VERSION 5.8 ;
BUSBITCHARS "[]" ;
DIVIDERCHAR "/" ;
UNITS
    DATABASE MICRONS 1000 ;
END UNITS

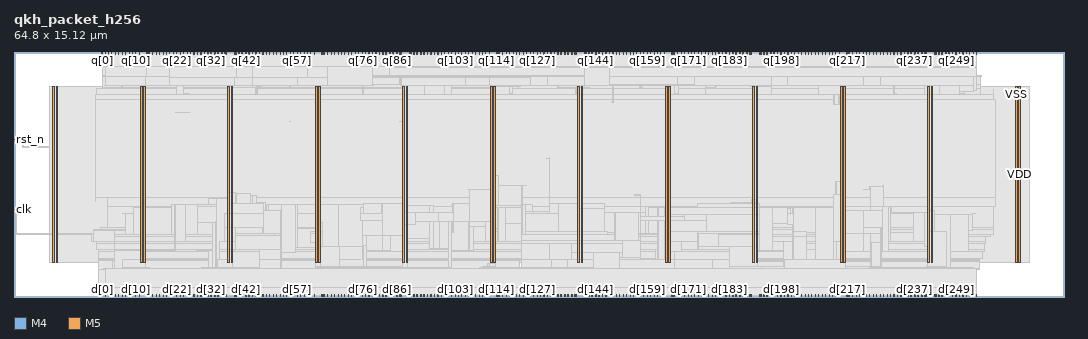
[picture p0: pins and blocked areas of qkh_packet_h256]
MACRO qkh_packet_h256
  FOREIGN qkh_packet_h256 0 0 ;
  CLASS BLOCK ;
  SIZE 64.8 BY 15.12 ;
  PIN clk
    DIRECTION INPUT ;
    USE SIGNAL ;
    PORT
      LAYER M4 ;
        RECT  0.054 5.376 0.138 5.4 ;
    END
    PORT
      LAYER M4 ;
        RECT  0.108 5.376 0.179 5.4 ;
    END
  END clk
  PIN d[0]
    DIRECTION INPUT ;
    USE SIGNAL ;
    PORT
      LAYER M5 ;
        RECT  5.424 0.054 5.448 0.138 ;
    END
  END d[0]
  PIN d[100]
    DIRECTION INPUT ;
    USE SIGNAL ;
    PORT
      LAYER M5 ;
        RECT  26.544 0.054 26.568 0.138 ;
    END
  END d[100]
  PIN d[101]
    DIRECTION INPUT ;
    USE SIGNAL ;
    PORT
      LAYER M5 ;
        RECT  26.784 0.054 26.808 0.138 ;
    END
  END d[101]
  PIN d[102]
    DIRECTION INPUT ;
    USE SIGNAL ;
    PORT
      LAYER M5 ;
        RECT  26.976 0.054 27 0.138 ;
    END
  END d[102]
  PIN d[103]
    DIRECTION INPUT ;
    USE SIGNAL ;
    PORT
      LAYER M5 ;
        RECT  27.216 0.054 27.24 0.138 ;
    END
  END d[103]
  PIN d[104]
    DIRECTION INPUT ;
    USE SIGNAL ;
    PORT
      LAYER M5 ;
        RECT  27.408 0.054 27.432 0.138 ;
    END
  END d[104]
  PIN d[105]
    DIRECTION INPUT ;
    USE SIGNAL ;
    PORT
      LAYER M5 ;
        RECT  27.6 0.054 27.624 0.138 ;
    END
  END d[105]
  PIN d[106]
    DIRECTION INPUT ;
    USE SIGNAL ;
    PORT
      LAYER M5 ;
        RECT  27.84 0.054 27.864 0.138 ;
    END
  END d[106]
  PIN d[107]
    DIRECTION INPUT ;
    USE SIGNAL ;
    PORT
      LAYER M5 ;
        RECT  28.032 0.054 28.056 0.138 ;
    END
  END d[107]
  PIN d[108]
    DIRECTION INPUT ;
    USE SIGNAL ;
    PORT
      LAYER M5 ;
        RECT  28.272 0.054 28.296 0.138 ;
    END
  END d[108]
  PIN d[109]
    DIRECTION INPUT ;
    USE SIGNAL ;
    PORT
      LAYER M5 ;
        RECT  28.464 0.054 28.488 0.138 ;
    END
  END d[109]
  PIN d[10]
    DIRECTION INPUT ;
    USE SIGNAL ;
    PORT
      LAYER M5 ;
        RECT  7.488 0.054 7.512 0.138 ;
    END
  END d[10]
  PIN d[110]
    DIRECTION INPUT ;
    USE SIGNAL ;
    PORT
      LAYER M5 ;
        RECT  28.704 0.054 28.728 0.138 ;
    END
  END d[110]
  PIN d[111]
    DIRECTION INPUT ;
    USE SIGNAL ;
    PORT
      LAYER M5 ;
        RECT  28.896 0.054 28.92 0.138 ;
    END
  END d[111]
  PIN d[112]
    DIRECTION INPUT ;
    USE SIGNAL ;
    PORT
      LAYER M5 ;
        RECT  29.088 0.054 29.112 0.138 ;
    END
  END d[112]
  PIN d[113]
    DIRECTION INPUT ;
    USE SIGNAL ;
    PORT
      LAYER M5 ;
        RECT  29.328 0.054 29.352 0.138 ;
    END
  END d[113]
  PIN d[114]
    DIRECTION INPUT ;
    USE SIGNAL ;
    PORT
      LAYER M5 ;
        RECT  29.76 0.054 29.784 0.138 ;
    END
  END d[114]
  PIN d[115]
    DIRECTION INPUT ;
    USE SIGNAL ;
    PORT
      LAYER M5 ;
        RECT  29.856 0.054 29.88 0.138 ;
    END
  END d[115]
  PIN d[116]
    DIRECTION INPUT ;
    USE SIGNAL ;
    PORT
      LAYER M5 ;
        RECT  29.952 0.054 29.976 0.138 ;
    END
  END d[116]
  PIN d[117]
    DIRECTION INPUT ;
    USE SIGNAL ;
    PORT
      LAYER M5 ;
        RECT  30.144 0.054 30.168 0.138 ;
    END
  END d[117]
  PIN d[118]
    DIRECTION INPUT ;
    USE SIGNAL ;
    PORT
      LAYER M5 ;
        RECT  30.384 0.054 30.408 0.138 ;
    END
  END d[118]
  PIN d[119]
    DIRECTION INPUT ;
    USE SIGNAL ;
    PORT
      LAYER M5 ;
        RECT  30.576 0.054 30.6 0.138 ;
    END
  END d[119]
  PIN d[11]
    DIRECTION INPUT ;
    USE SIGNAL ;
    PORT
      LAYER M5 ;
        RECT  7.728 0.054 7.752 0.138 ;
    END
  END d[11]
  PIN d[120]
    DIRECTION INPUT ;
    USE SIGNAL ;
    PORT
      LAYER M5 ;
        RECT  30.816 0.054 30.84 0.138 ;
    END
  END d[120]
  PIN d[121]
    DIRECTION INPUT ;
    USE SIGNAL ;
    PORT
      LAYER M5 ;
        RECT  31.008 0.054 31.032 0.138 ;
    END
  END d[121]
  PIN d[122]
    DIRECTION INPUT ;
    USE SIGNAL ;
    PORT
      LAYER M5 ;
        RECT  31.2 0.054 31.224 0.138 ;
    END
  END d[122]
  PIN d[123]
    DIRECTION INPUT ;
    USE SIGNAL ;
    PORT
      LAYER M5 ;
        RECT  31.44 0.054 31.464 0.138 ;
    END
  END d[123]
  PIN d[124]
    DIRECTION INPUT ;
    USE SIGNAL ;
    PORT
      LAYER M5 ;
        RECT  31.632 0.054 31.656 0.138 ;
    END
  END d[124]
  PIN d[125]
    DIRECTION INPUT ;
    USE SIGNAL ;
    PORT
      LAYER M5 ;
        RECT  31.872 0.054 31.896 0.138 ;
    END
  END d[125]
  PIN d[126]
    DIRECTION INPUT ;
    USE SIGNAL ;
    PORT
      LAYER M5 ;
        RECT  32.064 0.054 32.088 0.138 ;
    END
  END d[126]
  PIN d[127]
    DIRECTION INPUT ;
    USE SIGNAL ;
    PORT
      LAYER M5 ;
        RECT  32.304 0.054 32.328 0.138 ;
    END
  END d[127]
  PIN d[128]
    DIRECTION INPUT ;
    USE SIGNAL ;
    PORT
      LAYER M5 ;
        RECT  32.496 0.054 32.52 0.138 ;
    END
  END d[128]
  PIN d[129]
    DIRECTION INPUT ;
    USE SIGNAL ;
    PORT
      LAYER M5 ;
        RECT  32.688 0.054 32.712 0.138 ;
    END
  END d[129]
  PIN d[12]
    DIRECTION INPUT ;
    USE SIGNAL ;
    PORT
      LAYER M5 ;
        RECT  8.16 0.054 8.184 0.138 ;
    END
  END d[12]
  PIN d[130]
    DIRECTION INPUT ;
    USE SIGNAL ;
    PORT
      LAYER M5 ;
        RECT  32.928 0.054 32.952 0.138 ;
    END
  END d[130]
  PIN d[131]
    DIRECTION INPUT ;
    USE SIGNAL ;
    PORT
      LAYER M5 ;
        RECT  33.12 0.054 33.144 0.138 ;
    END
  END d[131]
  PIN d[132]
    DIRECTION INPUT ;
    USE SIGNAL ;
    PORT
      LAYER M5 ;
        RECT  33.36 0.054 33.384 0.138 ;
    END
  END d[132]
  PIN d[133]
    DIRECTION INPUT ;
    USE SIGNAL ;
    PORT
      LAYER M5 ;
        RECT  33.552 0.054 33.576 0.138 ;
    END
  END d[133]
  PIN d[134]
    DIRECTION INPUT ;
    USE SIGNAL ;
    PORT
      LAYER M5 ;
        RECT  33.744 0.054 33.768 0.138 ;
    END
  END d[134]
  PIN d[135]
    DIRECTION INPUT ;
    USE SIGNAL ;
    PORT
      LAYER M5 ;
        RECT  33.984 0.054 34.008 0.138 ;
    END
  END d[135]
  PIN d[136]
    DIRECTION INPUT ;
    USE SIGNAL ;
    PORT
      LAYER M5 ;
        RECT  34.176 0.054 34.2 0.138 ;
    END
  END d[136]
  PIN d[137]
    DIRECTION INPUT ;
    USE SIGNAL ;
    PORT
      LAYER M5 ;
        RECT  34.416 0.054 34.44 0.138 ;
    END
  END d[137]
  PIN d[138]
    DIRECTION INPUT ;
    USE SIGNAL ;
    PORT
      LAYER M5 ;
        RECT  34.608 0.054 34.632 0.138 ;
    END
  END d[138]
  PIN d[139]
    DIRECTION INPUT ;
    USE SIGNAL ;
    PORT
      LAYER M5 ;
        RECT  34.704 0.054 34.728 0.138 ;
    END
  END d[139]
  PIN d[13]
    DIRECTION INPUT ;
    USE SIGNAL ;
    PORT
      LAYER M5 ;
        RECT  8.256 0.054 8.28 0.138 ;
    END
  END d[13]
  PIN d[140]
    DIRECTION INPUT ;
    USE SIGNAL ;
    PORT
      LAYER M5 ;
        RECT  35.184 0.054 35.208 0.138 ;
    END
  END d[140]
  PIN d[141]
    DIRECTION INPUT ;
    USE SIGNAL ;
    PORT
      LAYER M5 ;
        RECT  35.28 0.054 35.304 0.138 ;
    END
  END d[141]
  PIN d[142]
    DIRECTION INPUT ;
    USE SIGNAL ;
    PORT
      LAYER M5 ;
        RECT  35.472 0.054 35.496 0.138 ;
    END
  END d[142]
  PIN d[143]
    DIRECTION INPUT ;
    USE SIGNAL ;
    PORT
      LAYER M5 ;
        RECT  35.664 0.054 35.688 0.138 ;
    END
  END d[143]
  PIN d[144]
    DIRECTION INPUT ;
    USE SIGNAL ;
    PORT
      LAYER M5 ;
        RECT  35.904 0.054 35.928 0.138 ;
    END
  END d[144]
  PIN d[145]
    DIRECTION INPUT ;
    USE SIGNAL ;
    PORT
      LAYER M5 ;
        RECT  36.096 0.054 36.12 0.138 ;
    END
  END d[145]
  PIN d[146]
    DIRECTION INPUT ;
    USE SIGNAL ;
    PORT
      LAYER M5 ;
        RECT  36.288 0.054 36.312 0.138 ;
    END
  END d[146]
  PIN d[147]
    DIRECTION INPUT ;
    USE SIGNAL ;
    PORT
      LAYER M5 ;
        RECT  36.528 0.054 36.552 0.138 ;
    END
  END d[147]
  PIN d[148]
    DIRECTION INPUT ;
    USE SIGNAL ;
    PORT
      LAYER M5 ;
        RECT  36.72 0.054 36.744 0.138 ;
    END
  END d[148]
  PIN d[149]
    DIRECTION INPUT ;
    USE SIGNAL ;
    PORT
      LAYER M5 ;
        RECT  36.96 0.054 36.984 0.138 ;
    END
  END d[149]
  PIN d[14]
    DIRECTION INPUT ;
    USE SIGNAL ;
    PORT
      LAYER M5 ;
        RECT  8.352 0.054 8.376 0.138 ;
    END
  END d[14]
  PIN d[150]
    DIRECTION INPUT ;
    USE SIGNAL ;
    PORT
      LAYER M5 ;
        RECT  37.152 0.054 37.176 0.138 ;
    END
  END d[150]
  PIN d[151]
    DIRECTION INPUT ;
    USE SIGNAL ;
    PORT
      LAYER M5 ;
        RECT  37.344 0.054 37.368 0.138 ;
    END
  END d[151]
  PIN d[152]
    DIRECTION INPUT ;
    USE SIGNAL ;
    PORT
      LAYER M5 ;
        RECT  37.584 0.054 37.608 0.138 ;
    END
  END d[152]
  PIN d[153]
    DIRECTION INPUT ;
    USE SIGNAL ;
    PORT
      LAYER M5 ;
        RECT  37.776 0.054 37.8 0.138 ;
    END
  END d[153]
  PIN d[154]
    DIRECTION INPUT ;
    USE SIGNAL ;
    PORT
      LAYER M5 ;
        RECT  38.016 0.054 38.04 0.138 ;
    END
  END d[154]
  PIN d[155]
    DIRECTION INPUT ;
    USE SIGNAL ;
    PORT
      LAYER M5 ;
        RECT  38.208 0.054 38.232 0.138 ;
    END
  END d[155]
  PIN d[156]
    DIRECTION INPUT ;
    USE SIGNAL ;
    PORT
      LAYER M5 ;
        RECT  38.4 0.054 38.424 0.138 ;
    END
  END d[156]
  PIN d[157]
    DIRECTION INPUT ;
    USE SIGNAL ;
    PORT
      LAYER M5 ;
        RECT  38.64 0.054 38.664 0.138 ;
    END
  END d[157]
  PIN d[158]
    DIRECTION INPUT ;
    USE SIGNAL ;
    PORT
      LAYER M5 ;
        RECT  38.832 0.054 38.856 0.138 ;
    END
  END d[158]
  PIN d[159]
    DIRECTION INPUT ;
    USE SIGNAL ;
    PORT
      LAYER M5 ;
        RECT  39.072 0.054 39.096 0.138 ;
    END
  END d[159]
  PIN d[15]
    DIRECTION INPUT ;
    USE SIGNAL ;
    PORT
      LAYER M5 ;
        RECT  8.544 0.054 8.568 0.138 ;
    END
  END d[15]
  PIN d[160]
    DIRECTION INPUT ;
    USE SIGNAL ;
    PORT
      LAYER M5 ;
        RECT  39.264 0.054 39.288 0.138 ;
    END
  END d[160]
  PIN d[161]
    DIRECTION INPUT ;
    USE SIGNAL ;
    PORT
      LAYER M5 ;
        RECT  39.504 0.054 39.528 0.138 ;
    END
  END d[161]
  PIN d[162]
    DIRECTION INPUT ;
    USE SIGNAL ;
    PORT
      LAYER M5 ;
        RECT  39.696 0.054 39.72 0.138 ;
    END
  END d[162]
  PIN d[163]
    DIRECTION INPUT ;
    USE SIGNAL ;
    PORT
      LAYER M5 ;
        RECT  39.888 0.054 39.912 0.138 ;
    END
  END d[163]
  PIN d[164]
    DIRECTION INPUT ;
    USE SIGNAL ;
    PORT
      LAYER M5 ;
        RECT  40.128 0.054 40.152 0.138 ;
    END
  END d[164]
  PIN d[165]
    DIRECTION INPUT ;
    USE SIGNAL ;
    PORT
      LAYER M5 ;
        RECT  40.56 0.054 40.584 0.138 ;
    END
  END d[165]
  PIN d[166]
    DIRECTION INPUT ;
    USE SIGNAL ;
    PORT
      LAYER M5 ;
        RECT  40.656 0.054 40.68 0.138 ;
    END
  END d[166]
  PIN d[167]
    DIRECTION INPUT ;
    USE SIGNAL ;
    PORT
      LAYER M5 ;
        RECT  40.752 0.054 40.776 0.138 ;
    END
  END d[167]
  PIN d[168]
    DIRECTION INPUT ;
    USE SIGNAL ;
    PORT
      LAYER M5 ;
        RECT  40.944 0.054 40.968 0.138 ;
    END
  END d[168]
  PIN d[169]
    DIRECTION INPUT ;
    USE SIGNAL ;
    PORT
      LAYER M5 ;
        RECT  41.184 0.054 41.208 0.138 ;
    END
  END d[169]
  PIN d[16]
    DIRECTION INPUT ;
    USE SIGNAL ;
    PORT
      LAYER M5 ;
        RECT  8.784 0.054 8.808 0.138 ;
    END
  END d[16]
  PIN d[170]
    DIRECTION INPUT ;
    USE SIGNAL ;
    PORT
      LAYER M5 ;
        RECT  41.376 0.054 41.4 0.138 ;
    END
  END d[170]
  PIN d[171]
    DIRECTION INPUT ;
    USE SIGNAL ;
    PORT
      LAYER M5 ;
        RECT  41.616 0.054 41.64 0.138 ;
    END
  END d[171]
  PIN d[172]
    DIRECTION INPUT ;
    USE SIGNAL ;
    PORT
      LAYER M5 ;
        RECT  41.808 0.054 41.832 0.138 ;
    END
  END d[172]
  PIN d[173]
    DIRECTION INPUT ;
    USE SIGNAL ;
    PORT
      LAYER M5 ;
        RECT  42 0.054 42.024 0.138 ;
    END
  END d[173]
  PIN d[174]
    DIRECTION INPUT ;
    USE SIGNAL ;
    PORT
      LAYER M5 ;
        RECT  42.24 0.054 42.264 0.138 ;
    END
  END d[174]
  PIN d[175]
    DIRECTION INPUT ;
    USE SIGNAL ;
    PORT
      LAYER M5 ;
        RECT  42.432 0.054 42.456 0.138 ;
    END
  END d[175]
  PIN d[176]
    DIRECTION INPUT ;
    USE SIGNAL ;
    PORT
      LAYER M5 ;
        RECT  42.672 0.054 42.696 0.138 ;
    END
  END d[176]
  PIN d[177]
    DIRECTION INPUT ;
    USE SIGNAL ;
    PORT
      LAYER M5 ;
        RECT  42.864 0.054 42.888 0.138 ;
    END
  END d[177]
  PIN d[178]
    DIRECTION INPUT ;
    USE SIGNAL ;
    PORT
      LAYER M5 ;
        RECT  43.104 0.054 43.128 0.138 ;
    END
  END d[178]
  PIN d[179]
    DIRECTION INPUT ;
    USE SIGNAL ;
    PORT
      LAYER M5 ;
        RECT  43.296 0.054 43.32 0.138 ;
    END
  END d[179]
  PIN d[17]
    DIRECTION INPUT ;
    USE SIGNAL ;
    PORT
      LAYER M5 ;
        RECT  8.976 0.054 9 0.138 ;
    END
  END d[17]
  PIN d[180]
    DIRECTION INPUT ;
    USE SIGNAL ;
    PORT
      LAYER M5 ;
        RECT  43.488 0.054 43.512 0.138 ;
    END
  END d[180]
  PIN d[181]
    DIRECTION INPUT ;
    USE SIGNAL ;
    PORT
      LAYER M5 ;
        RECT  43.728 0.054 43.752 0.138 ;
    END
  END d[181]
  PIN d[182]
    DIRECTION INPUT ;
    USE SIGNAL ;
    PORT
      LAYER M5 ;
        RECT  43.92 0.054 43.944 0.138 ;
    END
  END d[182]
  PIN d[183]
    DIRECTION INPUT ;
    USE SIGNAL ;
    PORT
      LAYER M5 ;
        RECT  44.16 0.054 44.184 0.138 ;
    END
  END d[183]
  PIN d[184]
    DIRECTION INPUT ;
    USE SIGNAL ;
    PORT
      LAYER M5 ;
        RECT  44.352 0.054 44.376 0.138 ;
    END
  END d[184]
  PIN d[185]
    DIRECTION INPUT ;
    USE SIGNAL ;
    PORT
      LAYER M5 ;
        RECT  44.544 0.054 44.568 0.138 ;
    END
  END d[185]
  PIN d[186]
    DIRECTION INPUT ;
    USE SIGNAL ;
    PORT
      LAYER M5 ;
        RECT  44.784 0.054 44.808 0.138 ;
    END
  END d[186]
  PIN d[187]
    DIRECTION INPUT ;
    USE SIGNAL ;
    PORT
      LAYER M5 ;
        RECT  44.976 0.054 45 0.138 ;
    END
  END d[187]
  PIN d[188]
    DIRECTION INPUT ;
    USE SIGNAL ;
    PORT
      LAYER M5 ;
        RECT  45.216 0.054 45.24 0.138 ;
    END
  END d[188]
  PIN d[189]
    DIRECTION INPUT ;
    USE SIGNAL ;
    PORT
      LAYER M5 ;
        RECT  45.408 0.054 45.432 0.138 ;
    END
  END d[189]
  PIN d[18]
    DIRECTION INPUT ;
    USE SIGNAL ;
    PORT
      LAYER M5 ;
        RECT  9.216 0.054 9.24 0.138 ;
    END
  END d[18]
  PIN d[190]
    DIRECTION INPUT ;
    USE SIGNAL ;
    PORT
      LAYER M5 ;
        RECT  45.504 0.054 45.528 0.138 ;
    END
  END d[190]
  PIN d[191]
    DIRECTION INPUT ;
    USE SIGNAL ;
    PORT
      LAYER M5 ;
        RECT  45.984 0.054 46.008 0.138 ;
    END
  END d[191]
  PIN d[192]
    DIRECTION INPUT ;
    USE SIGNAL ;
    PORT
      LAYER M5 ;
        RECT  46.08 0.054 46.104 0.138 ;
    END
  END d[192]
  PIN d[193]
    DIRECTION INPUT ;
    USE SIGNAL ;
    PORT
      LAYER M5 ;
        RECT  46.272 0.054 46.296 0.138 ;
    END
  END d[193]
  PIN d[194]
    DIRECTION INPUT ;
    USE SIGNAL ;
    PORT
      LAYER M5 ;
        RECT  46.464 0.054 46.488 0.138 ;
    END
  END d[194]
  PIN d[195]
    DIRECTION INPUT ;
    USE SIGNAL ;
    PORT
      LAYER M5 ;
        RECT  46.704 0.054 46.728 0.138 ;
    END
  END d[195]
  PIN d[196]
    DIRECTION INPUT ;
    USE SIGNAL ;
    PORT
      LAYER M5 ;
        RECT  46.896 0.054 46.92 0.138 ;
    END
  END d[196]
  PIN d[197]
    DIRECTION INPUT ;
    USE SIGNAL ;
    PORT
      LAYER M5 ;
        RECT  47.088 0.054 47.112 0.138 ;
    END
  END d[197]
  PIN d[198]
    DIRECTION INPUT ;
    USE SIGNAL ;
    PORT
      LAYER M5 ;
        RECT  47.328 0.054 47.352 0.138 ;
    END
  END d[198]
  PIN d[199]
    DIRECTION INPUT ;
    USE SIGNAL ;
    PORT
      LAYER M5 ;
        RECT  47.52 0.054 47.544 0.138 ;
    END
  END d[199]
  PIN d[19]
    DIRECTION INPUT ;
    USE SIGNAL ;
    PORT
      LAYER M5 ;
        RECT  9.408 0.054 9.432 0.138 ;
    END
  END d[19]
  PIN d[1]
    DIRECTION INPUT ;
    USE SIGNAL ;
    PORT
      LAYER M5 ;
        RECT  5.616 0.054 5.64 0.138 ;
    END
  END d[1]
  PIN d[200]
    DIRECTION INPUT ;
    USE SIGNAL ;
    PORT
      LAYER M5 ;
        RECT  47.76 0.054 47.784 0.138 ;
    END
  END d[200]
  PIN d[201]
    DIRECTION INPUT ;
    USE SIGNAL ;
    PORT
      LAYER M5 ;
        RECT  47.952 0.054 47.976 0.138 ;
    END
  END d[201]
  PIN d[202]
    DIRECTION INPUT ;
    USE SIGNAL ;
    PORT
      LAYER M5 ;
        RECT  48.144 0.054 48.168 0.138 ;
    END
  END d[202]
  PIN d[203]
    DIRECTION INPUT ;
    USE SIGNAL ;
    PORT
      LAYER M5 ;
        RECT  48.384 0.054 48.408 0.138 ;
    END
  END d[203]
  PIN d[204]
    DIRECTION INPUT ;
    USE SIGNAL ;
    PORT
      LAYER M5 ;
        RECT  48.576 0.054 48.6 0.138 ;
    END
  END d[204]
  PIN d[205]
    DIRECTION INPUT ;
    USE SIGNAL ;
    PORT
      LAYER M5 ;
        RECT  48.816 0.054 48.84 0.138 ;
    END
  END d[205]
  PIN d[206]
    DIRECTION INPUT ;
    USE SIGNAL ;
    PORT
      LAYER M5 ;
        RECT  49.008 0.054 49.032 0.138 ;
    END
  END d[206]
  PIN d[207]
    DIRECTION INPUT ;
    USE SIGNAL ;
    PORT
      LAYER M5 ;
        RECT  49.2 0.054 49.224 0.138 ;
    END
  END d[207]
  PIN d[208]
    DIRECTION INPUT ;
    USE SIGNAL ;
    PORT
      LAYER M5 ;
        RECT  49.44 0.054 49.464 0.138 ;
    END
  END d[208]
  PIN d[209]
    DIRECTION INPUT ;
    USE SIGNAL ;
    PORT
      LAYER M5 ;
        RECT  49.632 0.054 49.656 0.138 ;
    END
  END d[209]
  PIN d[20]
    DIRECTION INPUT ;
    USE SIGNAL ;
    PORT
      LAYER M5 ;
        RECT  9.6 0.054 9.624 0.138 ;
    END
  END d[20]
  PIN d[210]
    DIRECTION INPUT ;
    USE SIGNAL ;
    PORT
      LAYER M5 ;
        RECT  49.872 0.054 49.896 0.138 ;
    END
  END d[210]
  PIN d[211]
    DIRECTION INPUT ;
    USE SIGNAL ;
    PORT
      LAYER M5 ;
        RECT  50.064 0.054 50.088 0.138 ;
    END
  END d[211]
  PIN d[212]
    DIRECTION INPUT ;
    USE SIGNAL ;
    PORT
      LAYER M5 ;
        RECT  50.304 0.054 50.328 0.138 ;
    END
  END d[212]
  PIN d[213]
    DIRECTION INPUT ;
    USE SIGNAL ;
    PORT
      LAYER M5 ;
        RECT  50.496 0.054 50.52 0.138 ;
    END
  END d[213]
  PIN d[214]
    DIRECTION INPUT ;
    USE SIGNAL ;
    PORT
      LAYER M5 ;
        RECT  50.688 0.054 50.712 0.138 ;
    END
  END d[214]
  PIN d[215]
    DIRECTION INPUT ;
    USE SIGNAL ;
    PORT
      LAYER M5 ;
        RECT  50.928 0.054 50.952 0.138 ;
    END
  END d[215]
  PIN d[216]
    DIRECTION INPUT ;
    USE SIGNAL ;
    PORT
      LAYER M5 ;
        RECT  51.36 0.054 51.384 0.138 ;
    END
  END d[216]
  PIN d[217]
    DIRECTION INPUT ;
    USE SIGNAL ;
    PORT
      LAYER M5 ;
        RECT  51.456 0.054 51.48 0.138 ;
    END
  END d[217]
  PIN d[218]
    DIRECTION INPUT ;
    USE SIGNAL ;
    PORT
      LAYER M5 ;
        RECT  51.552 0.054 51.576 0.138 ;
    END
  END d[218]
  PIN d[219]
    DIRECTION INPUT ;
    USE SIGNAL ;
    PORT
      LAYER M5 ;
        RECT  51.744 0.054 51.768 0.138 ;
    END
  END d[219]
  PIN d[21]
    DIRECTION INPUT ;
    USE SIGNAL ;
    PORT
      LAYER M5 ;
        RECT  9.84 0.054 9.864 0.138 ;
    END
  END d[21]
  PIN d[220]
    DIRECTION INPUT ;
    USE SIGNAL ;
    PORT
      LAYER M5 ;
        RECT  51.984 0.054 52.008 0.138 ;
    END
  END d[220]
  PIN d[221]
    DIRECTION INPUT ;
    USE SIGNAL ;
    PORT
      LAYER M5 ;
        RECT  52.176 0.054 52.2 0.138 ;
    END
  END d[221]
  PIN d[222]
    DIRECTION INPUT ;
    USE SIGNAL ;
    PORT
      LAYER M5 ;
        RECT  52.416 0.054 52.44 0.138 ;
    END
  END d[222]
  PIN d[223]
    DIRECTION INPUT ;
    USE SIGNAL ;
    PORT
      LAYER M5 ;
        RECT  52.608 0.054 52.632 0.138 ;
    END
  END d[223]
  PIN d[224]
    DIRECTION INPUT ;
    USE SIGNAL ;
    PORT
      LAYER M5 ;
        RECT  52.8 0.054 52.824 0.138 ;
    END
  END d[224]
  PIN d[225]
    DIRECTION INPUT ;
    USE SIGNAL ;
    PORT
      LAYER M5 ;
        RECT  53.04 0.054 53.064 0.138 ;
    END
  END d[225]
  PIN d[226]
    DIRECTION INPUT ;
    USE SIGNAL ;
    PORT
      LAYER M5 ;
        RECT  53.232 0.054 53.256 0.138 ;
    END
  END d[226]
  PIN d[227]
    DIRECTION INPUT ;
    USE SIGNAL ;
    PORT
      LAYER M5 ;
        RECT  53.472 0.054 53.496 0.138 ;
    END
  END d[227]
  PIN d[228]
    DIRECTION INPUT ;
    USE SIGNAL ;
    PORT
      LAYER M5 ;
        RECT  53.664 0.054 53.688 0.138 ;
    END
  END d[228]
  PIN d[229]
    DIRECTION INPUT ;
    USE SIGNAL ;
    PORT
      LAYER M5 ;
        RECT  53.904 0.054 53.928 0.138 ;
    END
  END d[229]
  PIN d[22]
    DIRECTION INPUT ;
    USE SIGNAL ;
    PORT
      LAYER M5 ;
        RECT  10.032 0.054 10.056 0.138 ;
    END
  END d[22]
  PIN d[230]
    DIRECTION INPUT ;
    USE SIGNAL ;
    PORT
      LAYER M5 ;
        RECT  54.096 0.054 54.12 0.138 ;
    END
  END d[230]
  PIN d[231]
    DIRECTION INPUT ;
    USE SIGNAL ;
    PORT
      LAYER M5 ;
        RECT  54.288 0.054 54.312 0.138 ;
    END
  END d[231]
  PIN d[232]
    DIRECTION INPUT ;
    USE SIGNAL ;
    PORT
      LAYER M5 ;
        RECT  54.528 0.054 54.552 0.138 ;
    END
  END d[232]
  PIN d[233]
    DIRECTION INPUT ;
    USE SIGNAL ;
    PORT
      LAYER M5 ;
        RECT  54.72 0.054 54.744 0.138 ;
    END
  END d[233]
  PIN d[234]
    DIRECTION INPUT ;
    USE SIGNAL ;
    PORT
      LAYER M5 ;
        RECT  54.96 0.054 54.984 0.138 ;
    END
  END d[234]
  PIN d[235]
    DIRECTION INPUT ;
    USE SIGNAL ;
    PORT
      LAYER M5 ;
        RECT  55.152 0.054 55.176 0.138 ;
    END
  END d[235]
  PIN d[236]
    DIRECTION INPUT ;
    USE SIGNAL ;
    PORT
      LAYER M5 ;
        RECT  55.344 0.054 55.368 0.138 ;
    END
  END d[236]
  PIN d[237]
    DIRECTION INPUT ;
    USE SIGNAL ;
    PORT
      LAYER M5 ;
        RECT  55.584 0.054 55.608 0.138 ;
    END
  END d[237]
  PIN d[238]
    DIRECTION INPUT ;
    USE SIGNAL ;
    PORT
      LAYER M5 ;
        RECT  55.776 0.054 55.8 0.138 ;
    END
  END d[238]
  PIN d[239]
    DIRECTION INPUT ;
    USE SIGNAL ;
    PORT
      LAYER M5 ;
        RECT  56.016 0.054 56.04 0.138 ;
    END
  END d[239]
  PIN d[23]
    DIRECTION INPUT ;
    USE SIGNAL ;
    PORT
      LAYER M5 ;
        RECT  10.272 0.054 10.296 0.138 ;
    END
  END d[23]
  PIN d[240]
    DIRECTION INPUT ;
    USE SIGNAL ;
    PORT
      LAYER M5 ;
        RECT  56.208 0.054 56.232 0.138 ;
    END
  END d[240]
  PIN d[241]
    DIRECTION INPUT ;
    USE SIGNAL ;
    PORT
      LAYER M5 ;
        RECT  56.304 0.054 56.328 0.138 ;
    END
  END d[241]
  PIN d[242]
    DIRECTION INPUT ;
    USE SIGNAL ;
    PORT
      LAYER M5 ;
        RECT  56.784 0.054 56.808 0.138 ;
    END
  END d[242]
  PIN d[243]
    DIRECTION INPUT ;
    USE SIGNAL ;
    PORT
      LAYER M5 ;
        RECT  56.88 0.054 56.904 0.138 ;
    END
  END d[243]
  PIN d[244]
    DIRECTION INPUT ;
    USE SIGNAL ;
    PORT
      LAYER M5 ;
        RECT  57.072 0.054 57.096 0.138 ;
    END
  END d[244]
  PIN d[245]
    DIRECTION INPUT ;
    USE SIGNAL ;
    PORT
      LAYER M5 ;
        RECT  57.264 0.054 57.288 0.138 ;
    END
  END d[245]
  PIN d[246]
    DIRECTION INPUT ;
    USE SIGNAL ;
    PORT
      LAYER M5 ;
        RECT  57.504 0.054 57.528 0.138 ;
    END
  END d[246]
  PIN d[247]
    DIRECTION INPUT ;
    USE SIGNAL ;
    PORT
      LAYER M5 ;
        RECT  57.696 0.054 57.72 0.138 ;
    END
  END d[247]
  PIN d[248]
    DIRECTION INPUT ;
    USE SIGNAL ;
    PORT
      LAYER M5 ;
        RECT  57.888 0.054 57.912 0.138 ;
    END
  END d[248]
  PIN d[249]
    DIRECTION INPUT ;
    USE SIGNAL ;
    PORT
      LAYER M5 ;
        RECT  58.128 0.054 58.152 0.138 ;
    END
  END d[249]
  PIN d[24]
    DIRECTION INPUT ;
    USE SIGNAL ;
    PORT
      LAYER M5 ;
        RECT  10.464 0.054 10.488 0.138 ;
    END
  END d[24]
  PIN d[250]
    DIRECTION INPUT ;
    USE SIGNAL ;
    PORT
      LAYER M5 ;
        RECT  58.32 0.054 58.344 0.138 ;
    END
  END d[250]
  PIN d[251]
    DIRECTION INPUT ;
    USE SIGNAL ;
    PORT
      LAYER M5 ;
        RECT  58.56 0.054 58.584 0.138 ;
    END
  END d[251]
  PIN d[252]
    DIRECTION INPUT ;
    USE SIGNAL ;
    PORT
      LAYER M5 ;
        RECT  58.752 0.054 58.776 0.138 ;
    END
  END d[252]
  PIN d[253]
    DIRECTION INPUT ;
    USE SIGNAL ;
    PORT
      LAYER M5 ;
        RECT  58.944 0.054 58.968 0.138 ;
    END
  END d[253]
  PIN d[254]
    DIRECTION INPUT ;
    USE SIGNAL ;
    PORT
      LAYER M5 ;
        RECT  59.184 0.054 59.208 0.138 ;
    END
  END d[254]
  PIN d[255]
    DIRECTION INPUT ;
    USE SIGNAL ;
    PORT
      LAYER M5 ;
        RECT  59.376 0.054 59.4 0.138 ;
    END
  END d[255]
  PIN d[25]
    DIRECTION INPUT ;
    USE SIGNAL ;
    PORT
      LAYER M5 ;
        RECT  10.704 0.054 10.728 0.138 ;
    END
  END d[25]
  PIN d[26]
    DIRECTION INPUT ;
    USE SIGNAL ;
    PORT
      LAYER M5 ;
        RECT  10.896 0.054 10.92 0.138 ;
    END
  END d[26]
  PIN d[27]
    DIRECTION INPUT ;
    USE SIGNAL ;
    PORT
      LAYER M5 ;
        RECT  11.088 0.054 11.112 0.138 ;
    END
  END d[27]
  PIN d[28]
    DIRECTION INPUT ;
    USE SIGNAL ;
    PORT
      LAYER M5 ;
        RECT  11.328 0.054 11.352 0.138 ;
    END
  END d[28]
  PIN d[29]
    DIRECTION INPUT ;
    USE SIGNAL ;
    PORT
      LAYER M5 ;
        RECT  11.52 0.054 11.544 0.138 ;
    END
  END d[29]
  PIN d[2]
    DIRECTION INPUT ;
    USE SIGNAL ;
    PORT
      LAYER M5 ;
        RECT  5.808 0.054 5.832 0.138 ;
    END
  END d[2]
  PIN d[30]
    DIRECTION INPUT ;
    USE SIGNAL ;
    PORT
      LAYER M5 ;
        RECT  11.76 0.054 11.784 0.138 ;
    END
  END d[30]
  PIN d[31]
    DIRECTION INPUT ;
    USE SIGNAL ;
    PORT
      LAYER M5 ;
        RECT  11.952 0.054 11.976 0.138 ;
    END
  END d[31]
  PIN d[32]
    DIRECTION INPUT ;
    USE SIGNAL ;
    PORT
      LAYER M5 ;
        RECT  12.144 0.054 12.168 0.138 ;
    END
  END d[32]
  PIN d[33]
    DIRECTION INPUT ;
    USE SIGNAL ;
    PORT
      LAYER M5 ;
        RECT  12.384 0.054 12.408 0.138 ;
    END
  END d[33]
  PIN d[34]
    DIRECTION INPUT ;
    USE SIGNAL ;
    PORT
      LAYER M5 ;
        RECT  12.576 0.054 12.6 0.138 ;
    END
  END d[34]
  PIN d[35]
    DIRECTION INPUT ;
    USE SIGNAL ;
    PORT
      LAYER M5 ;
        RECT  12.816 0.054 12.84 0.138 ;
    END
  END d[35]
  PIN d[36]
    DIRECTION INPUT ;
    USE SIGNAL ;
    PORT
      LAYER M5 ;
        RECT  13.008 0.054 13.032 0.138 ;
    END
  END d[36]
  PIN d[37]
    DIRECTION INPUT ;
    USE SIGNAL ;
    PORT
      LAYER M5 ;
        RECT  13.104 0.054 13.128 0.138 ;
    END
  END d[37]
  PIN d[38]
    DIRECTION INPUT ;
    USE SIGNAL ;
    PORT
      LAYER M5 ;
        RECT  13.584 0.054 13.608 0.138 ;
    END
  END d[38]
  PIN d[39]
    DIRECTION INPUT ;
    USE SIGNAL ;
    PORT
      LAYER M5 ;
        RECT  13.68 0.054 13.704 0.138 ;
    END
  END d[39]
  PIN d[3]
    DIRECTION INPUT ;
    USE SIGNAL ;
    PORT
      LAYER M5 ;
        RECT  6 0.054 6.024 0.138 ;
    END
  END d[3]
  PIN d[40]
    DIRECTION INPUT ;
    USE SIGNAL ;
    PORT
      LAYER M5 ;
        RECT  13.872 0.054 13.896 0.138 ;
    END
  END d[40]
  PIN d[41]
    DIRECTION INPUT ;
    USE SIGNAL ;
    PORT
      LAYER M5 ;
        RECT  14.064 0.054 14.088 0.138 ;
    END
  END d[41]
  PIN d[42]
    DIRECTION INPUT ;
    USE SIGNAL ;
    PORT
      LAYER M5 ;
        RECT  14.304 0.054 14.328 0.138 ;
    END
  END d[42]
  PIN d[43]
    DIRECTION INPUT ;
    USE SIGNAL ;
    PORT
      LAYER M5 ;
        RECT  14.496 0.054 14.52 0.138 ;
    END
  END d[43]
  PIN d[44]
    DIRECTION INPUT ;
    USE SIGNAL ;
    PORT
      LAYER M5 ;
        RECT  14.688 0.054 14.712 0.138 ;
    END
  END d[44]
  PIN d[45]
    DIRECTION INPUT ;
    USE SIGNAL ;
    PORT
      LAYER M5 ;
        RECT  14.928 0.054 14.952 0.138 ;
    END
  END d[45]
  PIN d[46]
    DIRECTION INPUT ;
    USE SIGNAL ;
    PORT
      LAYER M5 ;
        RECT  15.12 0.054 15.144 0.138 ;
    END
  END d[46]
  PIN d[47]
    DIRECTION INPUT ;
    USE SIGNAL ;
    PORT
      LAYER M5 ;
        RECT  15.36 0.054 15.384 0.138 ;
    END
  END d[47]
  PIN d[48]
    DIRECTION INPUT ;
    USE SIGNAL ;
    PORT
      LAYER M5 ;
        RECT  15.552 0.054 15.576 0.138 ;
    END
  END d[48]
  PIN d[49]
    DIRECTION INPUT ;
    USE SIGNAL ;
    PORT
      LAYER M5 ;
        RECT  15.744 0.054 15.768 0.138 ;
    END
  END d[49]
  PIN d[4]
    DIRECTION INPUT ;
    USE SIGNAL ;
    PORT
      LAYER M5 ;
        RECT  6.24 0.054 6.264 0.138 ;
    END
  END d[4]
  PIN d[50]
    DIRECTION INPUT ;
    USE SIGNAL ;
    PORT
      LAYER M5 ;
        RECT  15.984 0.054 16.008 0.138 ;
    END
  END d[50]
  PIN d[51]
    DIRECTION INPUT ;
    USE SIGNAL ;
    PORT
      LAYER M5 ;
        RECT  16.176 0.054 16.2 0.138 ;
    END
  END d[51]
  PIN d[52]
    DIRECTION INPUT ;
    USE SIGNAL ;
    PORT
      LAYER M5 ;
        RECT  16.416 0.054 16.44 0.138 ;
    END
  END d[52]
  PIN d[53]
    DIRECTION INPUT ;
    USE SIGNAL ;
    PORT
      LAYER M5 ;
        RECT  16.608 0.054 16.632 0.138 ;
    END
  END d[53]
  PIN d[54]
    DIRECTION INPUT ;
    USE SIGNAL ;
    PORT
      LAYER M5 ;
        RECT  16.8 0.054 16.824 0.138 ;
    END
  END d[54]
  PIN d[55]
    DIRECTION INPUT ;
    USE SIGNAL ;
    PORT
      LAYER M5 ;
        RECT  17.04 0.054 17.064 0.138 ;
    END
  END d[55]
  PIN d[56]
    DIRECTION INPUT ;
    USE SIGNAL ;
    PORT
      LAYER M5 ;
        RECT  17.232 0.054 17.256 0.138 ;
    END
  END d[56]
  PIN d[57]
    DIRECTION INPUT ;
    USE SIGNAL ;
    PORT
      LAYER M5 ;
        RECT  17.472 0.054 17.496 0.138 ;
    END
  END d[57]
  PIN d[58]
    DIRECTION INPUT ;
    USE SIGNAL ;
    PORT
      LAYER M5 ;
        RECT  17.664 0.054 17.688 0.138 ;
    END
  END d[58]
  PIN d[59]
    DIRECTION INPUT ;
    USE SIGNAL ;
    PORT
      LAYER M5 ;
        RECT  17.904 0.054 17.928 0.138 ;
    END
  END d[59]
  PIN d[5]
    DIRECTION INPUT ;
    USE SIGNAL ;
    PORT
      LAYER M5 ;
        RECT  6.432 0.054 6.456 0.138 ;
    END
  END d[5]
  PIN d[60]
    DIRECTION INPUT ;
    USE SIGNAL ;
    PORT
      LAYER M5 ;
        RECT  18.096 0.054 18.12 0.138 ;
    END
  END d[60]
  PIN d[61]
    DIRECTION INPUT ;
    USE SIGNAL ;
    PORT
      LAYER M5 ;
        RECT  18.288 0.054 18.312 0.138 ;
    END
  END d[61]
  PIN d[62]
    DIRECTION INPUT ;
    USE SIGNAL ;
    PORT
      LAYER M5 ;
        RECT  18.528 0.054 18.552 0.138 ;
    END
  END d[62]
  PIN d[63]
    DIRECTION INPUT ;
    USE SIGNAL ;
    PORT
      LAYER M5 ;
        RECT  18.96 0.054 18.984 0.138 ;
    END
  END d[63]
  PIN d[64]
    DIRECTION INPUT ;
    USE SIGNAL ;
    PORT
      LAYER M5 ;
        RECT  19.056 0.054 19.08 0.138 ;
    END
  END d[64]
  PIN d[65]
    DIRECTION INPUT ;
    USE SIGNAL ;
    PORT
      LAYER M5 ;
        RECT  19.152 0.054 19.176 0.138 ;
    END
  END d[65]
  PIN d[66]
    DIRECTION INPUT ;
    USE SIGNAL ;
    PORT
      LAYER M5 ;
        RECT  19.344 0.054 19.368 0.138 ;
    END
  END d[66]
  PIN d[67]
    DIRECTION INPUT ;
    USE SIGNAL ;
    PORT
      LAYER M5 ;
        RECT  19.584 0.054 19.608 0.138 ;
    END
  END d[67]
  PIN d[68]
    DIRECTION INPUT ;
    USE SIGNAL ;
    PORT
      LAYER M5 ;
        RECT  19.776 0.054 19.8 0.138 ;
    END
  END d[68]
  PIN d[69]
    DIRECTION INPUT ;
    USE SIGNAL ;
    PORT
      LAYER M5 ;
        RECT  20.016 0.054 20.04 0.138 ;
    END
  END d[69]
  PIN d[6]
    DIRECTION INPUT ;
    USE SIGNAL ;
    PORT
      LAYER M5 ;
        RECT  6.672 0.054 6.696 0.138 ;
    END
  END d[6]
  PIN d[70]
    DIRECTION INPUT ;
    USE SIGNAL ;
    PORT
      LAYER M5 ;
        RECT  20.208 0.054 20.232 0.138 ;
    END
  END d[70]
  PIN d[71]
    DIRECTION INPUT ;
    USE SIGNAL ;
    PORT
      LAYER M5 ;
        RECT  20.4 0.054 20.424 0.138 ;
    END
  END d[71]
  PIN d[72]
    DIRECTION INPUT ;
    USE SIGNAL ;
    PORT
      LAYER M5 ;
        RECT  20.64 0.054 20.664 0.138 ;
    END
  END d[72]
  PIN d[73]
    DIRECTION INPUT ;
    USE SIGNAL ;
    PORT
      LAYER M5 ;
        RECT  20.832 0.054 20.856 0.138 ;
    END
  END d[73]
  PIN d[74]
    DIRECTION INPUT ;
    USE SIGNAL ;
    PORT
      LAYER M5 ;
        RECT  21.072 0.054 21.096 0.138 ;
    END
  END d[74]
  PIN d[75]
    DIRECTION INPUT ;
    USE SIGNAL ;
    PORT
      LAYER M5 ;
        RECT  21.264 0.054 21.288 0.138 ;
    END
  END d[75]
  PIN d[76]
    DIRECTION INPUT ;
    USE SIGNAL ;
    PORT
      LAYER M5 ;
        RECT  21.504 0.054 21.528 0.138 ;
    END
  END d[76]
  PIN d[77]
    DIRECTION INPUT ;
    USE SIGNAL ;
    PORT
      LAYER M5 ;
        RECT  21.696 0.054 21.72 0.138 ;
    END
  END d[77]
  PIN d[78]
    DIRECTION INPUT ;
    USE SIGNAL ;
    PORT
      LAYER M5 ;
        RECT  21.888 0.054 21.912 0.138 ;
    END
  END d[78]
  PIN d[79]
    DIRECTION INPUT ;
    USE SIGNAL ;
    PORT
      LAYER M5 ;
        RECT  22.128 0.054 22.152 0.138 ;
    END
  END d[79]
  PIN d[7]
    DIRECTION INPUT ;
    USE SIGNAL ;
    PORT
      LAYER M5 ;
        RECT  6.864 0.054 6.888 0.138 ;
    END
  END d[7]
  PIN d[80]
    DIRECTION INPUT ;
    USE SIGNAL ;
    PORT
      LAYER M5 ;
        RECT  22.32 0.054 22.344 0.138 ;
    END
  END d[80]
  PIN d[81]
    DIRECTION INPUT ;
    USE SIGNAL ;
    PORT
      LAYER M5 ;
        RECT  22.56 0.054 22.584 0.138 ;
    END
  END d[81]
  PIN d[82]
    DIRECTION INPUT ;
    USE SIGNAL ;
    PORT
      LAYER M5 ;
        RECT  22.752 0.054 22.776 0.138 ;
    END
  END d[82]
  PIN d[83]
    DIRECTION INPUT ;
    USE SIGNAL ;
    PORT
      LAYER M5 ;
        RECT  22.944 0.054 22.968 0.138 ;
    END
  END d[83]
  PIN d[84]
    DIRECTION INPUT ;
    USE SIGNAL ;
    PORT
      LAYER M5 ;
        RECT  23.184 0.054 23.208 0.138 ;
    END
  END d[84]
  PIN d[85]
    DIRECTION INPUT ;
    USE SIGNAL ;
    PORT
      LAYER M5 ;
        RECT  23.376 0.054 23.4 0.138 ;
    END
  END d[85]
  PIN d[86]
    DIRECTION INPUT ;
    USE SIGNAL ;
    PORT
      LAYER M5 ;
        RECT  23.616 0.054 23.64 0.138 ;
    END
  END d[86]
  PIN d[87]
    DIRECTION INPUT ;
    USE SIGNAL ;
    PORT
      LAYER M5 ;
        RECT  23.808 0.054 23.832 0.138 ;
    END
  END d[87]
  PIN d[88]
    DIRECTION INPUT ;
    USE SIGNAL ;
    PORT
      LAYER M5 ;
        RECT  23.904 0.054 23.928 0.138 ;
    END
  END d[88]
  PIN d[89]
    DIRECTION INPUT ;
    USE SIGNAL ;
    PORT
      LAYER M5 ;
        RECT  24.384 0.054 24.408 0.138 ;
    END
  END d[89]
  PIN d[8]
    DIRECTION INPUT ;
    USE SIGNAL ;
    PORT
      LAYER M5 ;
        RECT  7.104 0.054 7.128 0.138 ;
    END
  END d[8]
  PIN d[90]
    DIRECTION INPUT ;
    USE SIGNAL ;
    PORT
      LAYER M5 ;
        RECT  24.48 0.054 24.504 0.138 ;
    END
  END d[90]
  PIN d[91]
    DIRECTION INPUT ;
    USE SIGNAL ;
    PORT
      LAYER M5 ;
        RECT  24.672 0.054 24.696 0.138 ;
    END
  END d[91]
  PIN d[92]
    DIRECTION INPUT ;
    USE SIGNAL ;
    PORT
      LAYER M5 ;
        RECT  24.864 0.054 24.888 0.138 ;
    END
  END d[92]
  PIN d[93]
    DIRECTION INPUT ;
    USE SIGNAL ;
    PORT
      LAYER M5 ;
        RECT  25.104 0.054 25.128 0.138 ;
    END
  END d[93]
  PIN d[94]
    DIRECTION INPUT ;
    USE SIGNAL ;
    PORT
      LAYER M5 ;
        RECT  25.296 0.054 25.32 0.138 ;
    END
  END d[94]
  PIN d[95]
    DIRECTION INPUT ;
    USE SIGNAL ;
    PORT
      LAYER M5 ;
        RECT  25.488 0.054 25.512 0.138 ;
    END
  END d[95]
  PIN d[96]
    DIRECTION INPUT ;
    USE SIGNAL ;
    PORT
      LAYER M5 ;
        RECT  25.728 0.054 25.752 0.138 ;
    END
  END d[96]
  PIN d[97]
    DIRECTION INPUT ;
    USE SIGNAL ;
    PORT
      LAYER M5 ;
        RECT  25.92 0.054 25.944 0.138 ;
    END
  END d[97]
  PIN d[98]
    DIRECTION INPUT ;
    USE SIGNAL ;
    PORT
      LAYER M5 ;
        RECT  26.16 0.054 26.184 0.138 ;
    END
  END d[98]
  PIN d[99]
    DIRECTION INPUT ;
    USE SIGNAL ;
    PORT
      LAYER M5 ;
        RECT  26.352 0.054 26.376 0.138 ;
    END
  END d[99]
  PIN d[9]
    DIRECTION INPUT ;
    USE SIGNAL ;
    PORT
      LAYER M5 ;
        RECT  7.296 0.054 7.32 0.138 ;
    END
  END d[9]
  PIN q[0]
    DIRECTION OUTPUT ;
    USE SIGNAL ;
    PORT
      LAYER M5 ;
        RECT  5.424 14.982 5.448 15.066 ;
    END
  END q[0]
  PIN q[100]
    DIRECTION OUTPUT ;
    USE SIGNAL ;
    PORT
      LAYER M5 ;
        RECT  26.544 14.982 26.568 15.066 ;
    END
  END q[100]
  PIN q[101]
    DIRECTION OUTPUT ;
    USE SIGNAL ;
    PORT
      LAYER M5 ;
        RECT  26.784 14.982 26.808 15.066 ;
    END
  END q[101]
  PIN q[102]
    DIRECTION OUTPUT ;
    USE SIGNAL ;
    PORT
      LAYER M5 ;
        RECT  26.976 14.982 27 15.066 ;
    END
  END q[102]
  PIN q[103]
    DIRECTION OUTPUT ;
    USE SIGNAL ;
    PORT
      LAYER M5 ;
        RECT  27.216 14.982 27.24 15.066 ;
    END
  END q[103]
  PIN q[104]
    DIRECTION OUTPUT ;
    USE SIGNAL ;
    PORT
      LAYER M5 ;
        RECT  27.408 14.982 27.432 15.066 ;
    END
  END q[104]
  PIN q[105]
    DIRECTION OUTPUT ;
    USE SIGNAL ;
    PORT
      LAYER M5 ;
        RECT  27.6 14.982 27.624 15.066 ;
    END
  END q[105]
  PIN q[106]
    DIRECTION OUTPUT ;
    USE SIGNAL ;
    PORT
      LAYER M5 ;
        RECT  27.84 14.982 27.864 15.066 ;
    END
  END q[106]
  PIN q[107]
    DIRECTION OUTPUT ;
    USE SIGNAL ;
    PORT
      LAYER M5 ;
        RECT  28.032 14.982 28.056 15.066 ;
    END
  END q[107]
  PIN q[108]
    DIRECTION OUTPUT ;
    USE SIGNAL ;
    PORT
      LAYER M5 ;
        RECT  28.272 14.982 28.296 15.066 ;
    END
  END q[108]
  PIN q[109]
    DIRECTION OUTPUT ;
    USE SIGNAL ;
    PORT
      LAYER M5 ;
        RECT  28.464 14.982 28.488 15.066 ;
    END
  END q[109]
  PIN q[10]
    DIRECTION OUTPUT ;
    USE SIGNAL ;
    PORT
      LAYER M5 ;
        RECT  7.488 14.982 7.512 15.066 ;
    END
  END q[10]
  PIN q[110]
    DIRECTION OUTPUT ;
    USE SIGNAL ;
    PORT
      LAYER M5 ;
        RECT  28.704 14.982 28.728 15.066 ;
    END
  END q[110]
  PIN q[111]
    DIRECTION OUTPUT ;
    USE SIGNAL ;
    PORT
      LAYER M5 ;
        RECT  28.896 14.982 28.92 15.066 ;
    END
  END q[111]
  PIN q[112]
    DIRECTION OUTPUT ;
    USE SIGNAL ;
    PORT
      LAYER M5 ;
        RECT  29.088 14.982 29.112 15.066 ;
    END
  END q[112]
  PIN q[113]
    DIRECTION OUTPUT ;
    USE SIGNAL ;
    PORT
      LAYER M5 ;
        RECT  29.328 14.982 29.352 15.066 ;
    END
  END q[113]
  PIN q[114]
    DIRECTION OUTPUT ;
    USE SIGNAL ;
    PORT
      LAYER M5 ;
        RECT  29.76 14.982 29.784 15.066 ;
    END
  END q[114]
  PIN q[115]
    DIRECTION OUTPUT ;
    USE SIGNAL ;
    PORT
      LAYER M5 ;
        RECT  29.856 14.982 29.88 15.066 ;
    END
  END q[115]
  PIN q[116]
    DIRECTION OUTPUT ;
    USE SIGNAL ;
    PORT
      LAYER M5 ;
        RECT  29.952 14.982 29.976 15.066 ;
    END
  END q[116]
  PIN q[117]
    DIRECTION OUTPUT ;
    USE SIGNAL ;
    PORT
      LAYER M5 ;
        RECT  30.144 14.982 30.168 15.066 ;
    END
  END q[117]
  PIN q[118]
    DIRECTION OUTPUT ;
    USE SIGNAL ;
    PORT
      LAYER M5 ;
        RECT  30.384 14.982 30.408 15.066 ;
    END
  END q[118]
  PIN q[119]
    DIRECTION OUTPUT ;
    USE SIGNAL ;
    PORT
      LAYER M5 ;
        RECT  30.576 14.982 30.6 15.066 ;
    END
  END q[119]
  PIN q[11]
    DIRECTION OUTPUT ;
    USE SIGNAL ;
    PORT
      LAYER M5 ;
        RECT  7.728 14.982 7.752 15.066 ;
    END
  END q[11]
  PIN q[120]
    DIRECTION OUTPUT ;
    USE SIGNAL ;
    PORT
      LAYER M5 ;
        RECT  30.816 14.982 30.84 15.066 ;
    END
  END q[120]
  PIN q[121]
    DIRECTION OUTPUT ;
    USE SIGNAL ;
    PORT
      LAYER M5 ;
        RECT  31.008 14.982 31.032 15.066 ;
    END
  END q[121]
  PIN q[122]
    DIRECTION OUTPUT ;
    USE SIGNAL ;
    PORT
      LAYER M5 ;
        RECT  31.2 14.982 31.224 15.066 ;
    END
  END q[122]
  PIN q[123]
    DIRECTION OUTPUT ;
    USE SIGNAL ;
    PORT
      LAYER M5 ;
        RECT  31.44 14.982 31.464 15.066 ;
    END
  END q[123]
  PIN q[124]
    DIRECTION OUTPUT ;
    USE SIGNAL ;
    PORT
      LAYER M5 ;
        RECT  31.632 14.982 31.656 15.066 ;
    END
  END q[124]
  PIN q[125]
    DIRECTION OUTPUT ;
    USE SIGNAL ;
    PORT
      LAYER M5 ;
        RECT  31.872 14.982 31.896 15.066 ;
    END
  END q[125]
  PIN q[126]
    DIRECTION OUTPUT ;
    USE SIGNAL ;
    PORT
      LAYER M5 ;
        RECT  32.064 14.982 32.088 15.066 ;
    END
  END q[126]
  PIN q[127]
    DIRECTION OUTPUT ;
    USE SIGNAL ;
    PORT
      LAYER M5 ;
        RECT  32.304 14.982 32.328 15.066 ;
    END
  END q[127]
  PIN q[128]
    DIRECTION OUTPUT ;
    USE SIGNAL ;
    PORT
      LAYER M5 ;
        RECT  32.496 14.982 32.52 15.066 ;
    END
  END q[128]
  PIN q[129]
    DIRECTION OUTPUT ;
    USE SIGNAL ;
    PORT
      LAYER M5 ;
        RECT  32.688 14.982 32.712 15.066 ;
    END
  END q[129]
  PIN q[12]
    DIRECTION OUTPUT ;
    USE SIGNAL ;
    PORT
      LAYER M5 ;
        RECT  8.16 14.982 8.184 15.066 ;
    END
  END q[12]
  PIN q[130]
    DIRECTION OUTPUT ;
    USE SIGNAL ;
    PORT
      LAYER M5 ;
        RECT  32.928 14.982 32.952 15.066 ;
    END
  END q[130]
  PIN q[131]
    DIRECTION OUTPUT ;
    USE SIGNAL ;
    PORT
      LAYER M5 ;
        RECT  33.12 14.982 33.144 15.066 ;
    END
  END q[131]
  PIN q[132]
    DIRECTION OUTPUT ;
    USE SIGNAL ;
    PORT
      LAYER M5 ;
        RECT  33.36 14.982 33.384 15.066 ;
    END
  END q[132]
  PIN q[133]
    DIRECTION OUTPUT ;
    USE SIGNAL ;
    PORT
      LAYER M5 ;
        RECT  33.552 14.982 33.576 15.066 ;
    END
  END q[133]
  PIN q[134]
    DIRECTION OUTPUT ;
    USE SIGNAL ;
    PORT
      LAYER M5 ;
        RECT  33.744 14.982 33.768 15.066 ;
    END
  END q[134]
  PIN q[135]
    DIRECTION OUTPUT ;
    USE SIGNAL ;
    PORT
      LAYER M5 ;
        RECT  33.984 14.982 34.008 15.066 ;
    END
  END q[135]
  PIN q[136]
    DIRECTION OUTPUT ;
    USE SIGNAL ;
    PORT
      LAYER M5 ;
        RECT  34.176 14.982 34.2 15.066 ;
    END
  END q[136]
  PIN q[137]
    DIRECTION OUTPUT ;
    USE SIGNAL ;
    PORT
      LAYER M5 ;
        RECT  34.416 14.982 34.44 15.066 ;
    END
  END q[137]
  PIN q[138]
    DIRECTION OUTPUT ;
    USE SIGNAL ;
    PORT
      LAYER M5 ;
        RECT  34.608 14.982 34.632 15.066 ;
    END
  END q[138]
  PIN q[139]
    DIRECTION OUTPUT ;
    USE SIGNAL ;
    PORT
      LAYER M5 ;
        RECT  34.704 14.982 34.728 15.066 ;
    END
  END q[139]
  PIN q[13]
    DIRECTION OUTPUT ;
    USE SIGNAL ;
    PORT
      LAYER M5 ;
        RECT  8.256 14.982 8.28 15.066 ;
    END
  END q[13]
  PIN q[140]
    DIRECTION OUTPUT ;
    USE SIGNAL ;
    PORT
      LAYER M5 ;
        RECT  35.184 14.982 35.208 15.066 ;
    END
  END q[140]
  PIN q[141]
    DIRECTION OUTPUT ;
    USE SIGNAL ;
    PORT
      LAYER M5 ;
        RECT  35.28 14.982 35.304 15.066 ;
    END
  END q[141]
  PIN q[142]
    DIRECTION OUTPUT ;
    USE SIGNAL ;
    PORT
      LAYER M5 ;
        RECT  35.472 14.982 35.496 15.066 ;
    END
  END q[142]
  PIN q[143]
    DIRECTION OUTPUT ;
    USE SIGNAL ;
    PORT
      LAYER M5 ;
        RECT  35.664 14.982 35.688 15.066 ;
    END
  END q[143]
  PIN q[144]
    DIRECTION OUTPUT ;
    USE SIGNAL ;
    PORT
      LAYER M5 ;
        RECT  35.904 14.982 35.928 15.066 ;
    END
  END q[144]
  PIN q[145]
    DIRECTION OUTPUT ;
    USE SIGNAL ;
    PORT
      LAYER M5 ;
        RECT  36.096 14.982 36.12 15.066 ;
    END
  END q[145]
  PIN q[146]
    DIRECTION OUTPUT ;
    USE SIGNAL ;
    PORT
      LAYER M5 ;
        RECT  36.288 14.982 36.312 15.066 ;
    END
  END q[146]
  PIN q[147]
    DIRECTION OUTPUT ;
    USE SIGNAL ;
    PORT
      LAYER M5 ;
        RECT  36.528 14.982 36.552 15.066 ;
    END
  END q[147]
  PIN q[148]
    DIRECTION OUTPUT ;
    USE SIGNAL ;
    PORT
      LAYER M5 ;
        RECT  36.72 14.982 36.744 15.066 ;
    END
  END q[148]
  PIN q[149]
    DIRECTION OUTPUT ;
    USE SIGNAL ;
    PORT
      LAYER M5 ;
        RECT  36.96 14.982 36.984 15.066 ;
    END
  END q[149]
  PIN q[14]
    DIRECTION OUTPUT ;
    USE SIGNAL ;
    PORT
      LAYER M5 ;
        RECT  8.352 14.982 8.376 15.066 ;
    END
  END q[14]
  PIN q[150]
    DIRECTION OUTPUT ;
    USE SIGNAL ;
    PORT
      LAYER M5 ;
        RECT  37.152 14.982 37.176 15.066 ;
    END
  END q[150]
  PIN q[151]
    DIRECTION OUTPUT ;
    USE SIGNAL ;
    PORT
      LAYER M5 ;
        RECT  37.344 14.982 37.368 15.066 ;
    END
  END q[151]
  PIN q[152]
    DIRECTION OUTPUT ;
    USE SIGNAL ;
    PORT
      LAYER M5 ;
        RECT  37.584 14.982 37.608 15.066 ;
    END
  END q[152]
  PIN q[153]
    DIRECTION OUTPUT ;
    USE SIGNAL ;
    PORT
      LAYER M5 ;
        RECT  37.776 14.982 37.8 15.066 ;
    END
  END q[153]
  PIN q[154]
    DIRECTION OUTPUT ;
    USE SIGNAL ;
    PORT
      LAYER M5 ;
        RECT  38.016 14.982 38.04 15.066 ;
    END
  END q[154]
  PIN q[155]
    DIRECTION OUTPUT ;
    USE SIGNAL ;
    PORT
      LAYER M5 ;
        RECT  38.208 14.982 38.232 15.066 ;
    END
  END q[155]
  PIN q[156]
    DIRECTION OUTPUT ;
    USE SIGNAL ;
    PORT
      LAYER M5 ;
        RECT  38.4 14.982 38.424 15.066 ;
    END
  END q[156]
  PIN q[157]
    DIRECTION OUTPUT ;
    USE SIGNAL ;
    PORT
      LAYER M5 ;
        RECT  38.64 14.982 38.664 15.066 ;
    END
  END q[157]
  PIN q[158]
    DIRECTION OUTPUT ;
    USE SIGNAL ;
    PORT
      LAYER M5 ;
        RECT  38.832 14.982 38.856 15.066 ;
    END
  END q[158]
  PIN q[159]
    DIRECTION OUTPUT ;
    USE SIGNAL ;
    PORT
      LAYER M5 ;
        RECT  39.072 14.982 39.096 15.066 ;
    END
  END q[159]
  PIN q[15]
    DIRECTION OUTPUT ;
    USE SIGNAL ;
    PORT
      LAYER M5 ;
        RECT  8.544 14.982 8.568 15.066 ;
    END
  END q[15]
  PIN q[160]
    DIRECTION OUTPUT ;
    USE SIGNAL ;
    PORT
      LAYER M5 ;
        RECT  39.264 14.982 39.288 15.066 ;
    END
  END q[160]
  PIN q[161]
    DIRECTION OUTPUT ;
    USE SIGNAL ;
    PORT
      LAYER M5 ;
        RECT  39.504 14.982 39.528 15.066 ;
    END
  END q[161]
  PIN q[162]
    DIRECTION OUTPUT ;
    USE SIGNAL ;
    PORT
      LAYER M5 ;
        RECT  39.696 14.982 39.72 15.066 ;
    END
  END q[162]
  PIN q[163]
    DIRECTION OUTPUT ;
    USE SIGNAL ;
    PORT
      LAYER M5 ;
        RECT  39.888 14.982 39.912 15.066 ;
    END
  END q[163]
  PIN q[164]
    DIRECTION OUTPUT ;
    USE SIGNAL ;
    PORT
      LAYER M5 ;
        RECT  40.128 14.982 40.152 15.066 ;
    END
  END q[164]
  PIN q[165]
    DIRECTION OUTPUT ;
    USE SIGNAL ;
    PORT
      LAYER M5 ;
        RECT  40.56 14.982 40.584 15.066 ;
    END
  END q[165]
  PIN q[166]
    DIRECTION OUTPUT ;
    USE SIGNAL ;
    PORT
      LAYER M5 ;
        RECT  40.656 14.982 40.68 15.066 ;
    END
  END q[166]
  PIN q[167]
    DIRECTION OUTPUT ;
    USE SIGNAL ;
    PORT
      LAYER M5 ;
        RECT  40.752 14.982 40.776 15.066 ;
    END
  END q[167]
  PIN q[168]
    DIRECTION OUTPUT ;
    USE SIGNAL ;
    PORT
      LAYER M5 ;
        RECT  40.944 14.982 40.968 15.066 ;
    END
  END q[168]
  PIN q[169]
    DIRECTION OUTPUT ;
    USE SIGNAL ;
    PORT
      LAYER M5 ;
        RECT  41.184 14.982 41.208 15.066 ;
    END
  END q[169]
  PIN q[16]
    DIRECTION OUTPUT ;
    USE SIGNAL ;
    PORT
      LAYER M5 ;
        RECT  8.784 14.982 8.808 15.066 ;
    END
  END q[16]
  PIN q[170]
    DIRECTION OUTPUT ;
    USE SIGNAL ;
    PORT
      LAYER M5 ;
        RECT  41.376 14.982 41.4 15.066 ;
    END
  END q[170]
  PIN q[171]
    DIRECTION OUTPUT ;
    USE SIGNAL ;
    PORT
      LAYER M5 ;
        RECT  41.616 14.982 41.64 15.066 ;
    END
  END q[171]
  PIN q[172]
    DIRECTION OUTPUT ;
    USE SIGNAL ;
    PORT
      LAYER M5 ;
        RECT  41.808 14.982 41.832 15.066 ;
    END
  END q[172]
  PIN q[173]
    DIRECTION OUTPUT ;
    USE SIGNAL ;
    PORT
      LAYER M5 ;
        RECT  42 14.982 42.024 15.066 ;
    END
  END q[173]
  PIN q[174]
    DIRECTION OUTPUT ;
    USE SIGNAL ;
    PORT
      LAYER M5 ;
        RECT  42.24 14.982 42.264 15.066 ;
    END
  END q[174]
  PIN q[175]
    DIRECTION OUTPUT ;
    USE SIGNAL ;
    PORT
      LAYER M5 ;
        RECT  42.432 14.982 42.456 15.066 ;
    END
  END q[175]
  PIN q[176]
    DIRECTION OUTPUT ;
    USE SIGNAL ;
    PORT
      LAYER M5 ;
        RECT  42.672 14.982 42.696 15.066 ;
    END
  END q[176]
  PIN q[177]
    DIRECTION OUTPUT ;
    USE SIGNAL ;
    PORT
      LAYER M5 ;
        RECT  42.864 14.982 42.888 15.066 ;
    END
  END q[177]
  PIN q[178]
    DIRECTION OUTPUT ;
    USE SIGNAL ;
    PORT
      LAYER M5 ;
        RECT  43.104 14.982 43.128 15.066 ;
    END
  END q[178]
  PIN q[179]
    DIRECTION OUTPUT ;
    USE SIGNAL ;
    PORT
      LAYER M5 ;
        RECT  43.296 14.982 43.32 15.066 ;
    END
  END q[179]
  PIN q[17]
    DIRECTION OUTPUT ;
    USE SIGNAL ;
    PORT
      LAYER M5 ;
        RECT  8.976 14.982 9 15.066 ;
    END
  END q[17]
  PIN q[180]
    DIRECTION OUTPUT ;
    USE SIGNAL ;
    PORT
      LAYER M5 ;
        RECT  43.488 14.982 43.512 15.066 ;
    END
  END q[180]
  PIN q[181]
    DIRECTION OUTPUT ;
    USE SIGNAL ;
    PORT
      LAYER M5 ;
        RECT  43.728 14.982 43.752 15.066 ;
    END
  END q[181]
  PIN q[182]
    DIRECTION OUTPUT ;
    USE SIGNAL ;
    PORT
      LAYER M5 ;
        RECT  43.92 14.982 43.944 15.066 ;
    END
  END q[182]
  PIN q[183]
    DIRECTION OUTPUT ;
    USE SIGNAL ;
    PORT
      LAYER M5 ;
        RECT  44.16 14.982 44.184 15.066 ;
    END
  END q[183]
  PIN q[184]
    DIRECTION OUTPUT ;
    USE SIGNAL ;
    PORT
      LAYER M5 ;
        RECT  44.352 14.982 44.376 15.066 ;
    END
  END q[184]
  PIN q[185]
    DIRECTION OUTPUT ;
    USE SIGNAL ;
    PORT
      LAYER M5 ;
        RECT  44.544 14.982 44.568 15.066 ;
    END
  END q[185]
  PIN q[186]
    DIRECTION OUTPUT ;
    USE SIGNAL ;
    PORT
      LAYER M5 ;
        RECT  44.784 14.982 44.808 15.066 ;
    END
  END q[186]
  PIN q[187]
    DIRECTION OUTPUT ;
    USE SIGNAL ;
    PORT
      LAYER M5 ;
        RECT  44.976 14.982 45 15.066 ;
    END
  END q[187]
  PIN q[188]
    DIRECTION OUTPUT ;
    USE SIGNAL ;
    PORT
      LAYER M5 ;
        RECT  45.216 14.982 45.24 15.066 ;
    END
  END q[188]
  PIN q[189]
    DIRECTION OUTPUT ;
    USE SIGNAL ;
    PORT
      LAYER M5 ;
        RECT  45.408 14.982 45.432 15.066 ;
    END
  END q[189]
  PIN q[18]
    DIRECTION OUTPUT ;
    USE SIGNAL ;
    PORT
      LAYER M5 ;
        RECT  9.216 14.982 9.24 15.066 ;
    END
  END q[18]
  PIN q[190]
    DIRECTION OUTPUT ;
    USE SIGNAL ;
    PORT
      LAYER M5 ;
        RECT  45.504 14.982 45.528 15.066 ;
    END
  END q[190]
  PIN q[191]
    DIRECTION OUTPUT ;
    USE SIGNAL ;
    PORT
      LAYER M5 ;
        RECT  45.984 14.982 46.008 15.066 ;
    END
  END q[191]
  PIN q[192]
    DIRECTION OUTPUT ;
    USE SIGNAL ;
    PORT
      LAYER M5 ;
        RECT  46.08 14.982 46.104 15.066 ;
    END
  END q[192]
  PIN q[193]
    DIRECTION OUTPUT ;
    USE SIGNAL ;
    PORT
      LAYER M5 ;
        RECT  46.272 14.982 46.296 15.066 ;
    END
  END q[193]
  PIN q[194]
    DIRECTION OUTPUT ;
    USE SIGNAL ;
    PORT
      LAYER M5 ;
        RECT  46.464 14.982 46.488 15.066 ;
    END
  END q[194]
  PIN q[195]
    DIRECTION OUTPUT ;
    USE SIGNAL ;
    PORT
      LAYER M5 ;
        RECT  46.704 14.982 46.728 15.066 ;
    END
  END q[195]
  PIN q[196]
    DIRECTION OUTPUT ;
    USE SIGNAL ;
    PORT
      LAYER M5 ;
        RECT  46.896 14.982 46.92 15.066 ;
    END
  END q[196]
  PIN q[197]
    DIRECTION OUTPUT ;
    USE SIGNAL ;
    PORT
      LAYER M5 ;
        RECT  47.088 14.982 47.112 15.066 ;
    END
  END q[197]
  PIN q[198]
    DIRECTION OUTPUT ;
    USE SIGNAL ;
    PORT
      LAYER M5 ;
        RECT  47.328 14.982 47.352 15.066 ;
    END
  END q[198]
  PIN q[199]
    DIRECTION OUTPUT ;
    USE SIGNAL ;
    PORT
      LAYER M5 ;
        RECT  47.52 14.982 47.544 15.066 ;
    END
  END q[199]
  PIN q[19]
    DIRECTION OUTPUT ;
    USE SIGNAL ;
    PORT
      LAYER M5 ;
        RECT  9.408 14.982 9.432 15.066 ;
    END
  END q[19]
  PIN q[1]
    DIRECTION OUTPUT ;
    USE SIGNAL ;
    PORT
      LAYER M5 ;
        RECT  5.616 14.982 5.64 15.066 ;
    END
  END q[1]
  PIN q[200]
    DIRECTION OUTPUT ;
    USE SIGNAL ;
    PORT
      LAYER M5 ;
        RECT  47.76 14.982 47.784 15.066 ;
    END
  END q[200]
  PIN q[201]
    DIRECTION OUTPUT ;
    USE SIGNAL ;
    PORT
      LAYER M5 ;
        RECT  47.952 14.982 47.976 15.066 ;
    END
  END q[201]
  PIN q[202]
    DIRECTION OUTPUT ;
    USE SIGNAL ;
    PORT
      LAYER M5 ;
        RECT  48.144 14.982 48.168 15.066 ;
    END
  END q[202]
  PIN q[203]
    DIRECTION OUTPUT ;
    USE SIGNAL ;
    PORT
      LAYER M5 ;
        RECT  48.384 14.982 48.408 15.066 ;
    END
  END q[203]
  PIN q[204]
    DIRECTION OUTPUT ;
    USE SIGNAL ;
    PORT
      LAYER M5 ;
        RECT  48.576 14.982 48.6 15.066 ;
    END
  END q[204]
  PIN q[205]
    DIRECTION OUTPUT ;
    USE SIGNAL ;
    PORT
      LAYER M5 ;
        RECT  48.816 14.982 48.84 15.066 ;
    END
  END q[205]
  PIN q[206]
    DIRECTION OUTPUT ;
    USE SIGNAL ;
    PORT
      LAYER M5 ;
        RECT  49.008 14.982 49.032 15.066 ;
    END
  END q[206]
  PIN q[207]
    DIRECTION OUTPUT ;
    USE SIGNAL ;
    PORT
      LAYER M5 ;
        RECT  49.2 14.982 49.224 15.066 ;
    END
  END q[207]
  PIN q[208]
    DIRECTION OUTPUT ;
    USE SIGNAL ;
    PORT
      LAYER M5 ;
        RECT  49.44 14.982 49.464 15.066 ;
    END
  END q[208]
  PIN q[209]
    DIRECTION OUTPUT ;
    USE SIGNAL ;
    PORT
      LAYER M5 ;
        RECT  49.632 14.982 49.656 15.066 ;
    END
  END q[209]
  PIN q[20]
    DIRECTION OUTPUT ;
    USE SIGNAL ;
    PORT
      LAYER M5 ;
        RECT  9.6 14.982 9.624 15.066 ;
    END
  END q[20]
  PIN q[210]
    DIRECTION OUTPUT ;
    USE SIGNAL ;
    PORT
      LAYER M5 ;
        RECT  49.872 14.982 49.896 15.066 ;
    END
  END q[210]
  PIN q[211]
    DIRECTION OUTPUT ;
    USE SIGNAL ;
    PORT
      LAYER M5 ;
        RECT  50.064 14.982 50.088 15.066 ;
    END
  END q[211]
  PIN q[212]
    DIRECTION OUTPUT ;
    USE SIGNAL ;
    PORT
      LAYER M5 ;
        RECT  50.304 14.982 50.328 15.066 ;
    END
  END q[212]
  PIN q[213]
    DIRECTION OUTPUT ;
    USE SIGNAL ;
    PORT
      LAYER M5 ;
        RECT  50.496 14.982 50.52 15.066 ;
    END
  END q[213]
  PIN q[214]
    DIRECTION OUTPUT ;
    USE SIGNAL ;
    PORT
      LAYER M5 ;
        RECT  50.688 14.982 50.712 15.066 ;
    END
  END q[214]
  PIN q[215]
    DIRECTION OUTPUT ;
    USE SIGNAL ;
    PORT
      LAYER M5 ;
        RECT  50.928 14.982 50.952 15.066 ;
    END
  END q[215]
  PIN q[216]
    DIRECTION OUTPUT ;
    USE SIGNAL ;
    PORT
      LAYER M5 ;
        RECT  51.36 14.982 51.384 15.066 ;
    END
  END q[216]
  PIN q[217]
    DIRECTION OUTPUT ;
    USE SIGNAL ;
    PORT
      LAYER M5 ;
        RECT  51.456 14.982 51.48 15.066 ;
    END
  END q[217]
  PIN q[218]
    DIRECTION OUTPUT ;
    USE SIGNAL ;
    PORT
      LAYER M5 ;
        RECT  51.552 14.982 51.576 15.066 ;
    END
  END q[218]
  PIN q[219]
    DIRECTION OUTPUT ;
    USE SIGNAL ;
    PORT
      LAYER M5 ;
        RECT  51.744 14.982 51.768 15.066 ;
    END
  END q[219]
  PIN q[21]
    DIRECTION OUTPUT ;
    USE SIGNAL ;
    PORT
      LAYER M5 ;
        RECT  9.84 14.982 9.864 15.066 ;
    END
  END q[21]
  PIN q[220]
    DIRECTION OUTPUT ;
    USE SIGNAL ;
    PORT
      LAYER M5 ;
        RECT  51.984 14.982 52.008 15.066 ;
    END
  END q[220]
  PIN q[221]
    DIRECTION OUTPUT ;
    USE SIGNAL ;
    PORT
      LAYER M5 ;
        RECT  52.176 14.982 52.2 15.066 ;
    END
  END q[221]
  PIN q[222]
    DIRECTION OUTPUT ;
    USE SIGNAL ;
    PORT
      LAYER M5 ;
        RECT  52.416 14.982 52.44 15.066 ;
    END
  END q[222]
  PIN q[223]
    DIRECTION OUTPUT ;
    USE SIGNAL ;
    PORT
      LAYER M5 ;
        RECT  52.608 14.982 52.632 15.066 ;
    END
  END q[223]
  PIN q[224]
    DIRECTION OUTPUT ;
    USE SIGNAL ;
    PORT
      LAYER M5 ;
        RECT  52.8 14.982 52.824 15.066 ;
    END
  END q[224]
  PIN q[225]
    DIRECTION OUTPUT ;
    USE SIGNAL ;
    PORT
      LAYER M5 ;
        RECT  53.04 14.982 53.064 15.066 ;
    END
  END q[225]
  PIN q[226]
    DIRECTION OUTPUT ;
    USE SIGNAL ;
    PORT
      LAYER M5 ;
        RECT  53.232 14.982 53.256 15.066 ;
    END
  END q[226]
  PIN q[227]
    DIRECTION OUTPUT ;
    USE SIGNAL ;
    PORT
      LAYER M5 ;
        RECT  53.472 14.982 53.496 15.066 ;
    END
  END q[227]
  PIN q[228]
    DIRECTION OUTPUT ;
    USE SIGNAL ;
    PORT
      LAYER M5 ;
        RECT  53.664 14.982 53.688 15.066 ;
    END
  END q[228]
  PIN q[229]
    DIRECTION OUTPUT ;
    USE SIGNAL ;
    PORT
      LAYER M5 ;
        RECT  53.904 14.982 53.928 15.066 ;
    END
  END q[229]
  PIN q[22]
    DIRECTION OUTPUT ;
    USE SIGNAL ;
    PORT
      LAYER M5 ;
        RECT  10.032 14.982 10.056 15.066 ;
    END
  END q[22]
  PIN q[230]
    DIRECTION OUTPUT ;
    USE SIGNAL ;
    PORT
      LAYER M5 ;
        RECT  54.096 14.982 54.12 15.066 ;
    END
  END q[230]
  PIN q[231]
    DIRECTION OUTPUT ;
    USE SIGNAL ;
    PORT
      LAYER M5 ;
        RECT  54.288 14.982 54.312 15.066 ;
    END
  END q[231]
  PIN q[232]
    DIRECTION OUTPUT ;
    USE SIGNAL ;
    PORT
      LAYER M5 ;
        RECT  54.528 14.982 54.552 15.066 ;
    END
  END q[232]
  PIN q[233]
    DIRECTION OUTPUT ;
    USE SIGNAL ;
    PORT
      LAYER M5 ;
        RECT  54.72 14.982 54.744 15.066 ;
    END
  END q[233]
  PIN q[234]
    DIRECTION OUTPUT ;
    USE SIGNAL ;
    PORT
      LAYER M5 ;
        RECT  54.96 14.982 54.984 15.066 ;
    END
  END q[234]
  PIN q[235]
    DIRECTION OUTPUT ;
    USE SIGNAL ;
    PORT
      LAYER M5 ;
        RECT  55.152 14.982 55.176 15.066 ;
    END
  END q[235]
  PIN q[236]
    DIRECTION OUTPUT ;
    USE SIGNAL ;
    PORT
      LAYER M5 ;
        RECT  55.344 14.982 55.368 15.066 ;
    END
  END q[236]
  PIN q[237]
    DIRECTION OUTPUT ;
    USE SIGNAL ;
    PORT
      LAYER M5 ;
        RECT  55.584 14.982 55.608 15.066 ;
    END
  END q[237]
  PIN q[238]
    DIRECTION OUTPUT ;
    USE SIGNAL ;
    PORT
      LAYER M5 ;
        RECT  55.776 14.982 55.8 15.066 ;
    END
  END q[238]
  PIN q[239]
    DIRECTION OUTPUT ;
    USE SIGNAL ;
    PORT
      LAYER M5 ;
        RECT  56.016 14.982 56.04 15.066 ;
    END
  END q[239]
  PIN q[23]
    DIRECTION OUTPUT ;
    USE SIGNAL ;
    PORT
      LAYER M5 ;
        RECT  10.272 14.982 10.296 15.066 ;
    END
  END q[23]
  PIN q[240]
    DIRECTION OUTPUT ;
    USE SIGNAL ;
    PORT
      LAYER M5 ;
        RECT  56.208 14.982 56.232 15.066 ;
    END
  END q[240]
  PIN q[241]
    DIRECTION OUTPUT ;
    USE SIGNAL ;
    PORT
      LAYER M5 ;
        RECT  56.304 14.982 56.328 15.066 ;
    END
  END q[241]
  PIN q[242]
    DIRECTION OUTPUT ;
    USE SIGNAL ;
    PORT
      LAYER M5 ;
        RECT  56.784 14.982 56.808 15.066 ;
    END
  END q[242]
  PIN q[243]
    DIRECTION OUTPUT ;
    USE SIGNAL ;
    PORT
      LAYER M5 ;
        RECT  56.88 14.982 56.904 15.066 ;
    END
  END q[243]
  PIN q[244]
    DIRECTION OUTPUT ;
    USE SIGNAL ;
    PORT
      LAYER M5 ;
        RECT  57.072 14.982 57.096 15.066 ;
    END
  END q[244]
  PIN q[245]
    DIRECTION OUTPUT ;
    USE SIGNAL ;
    PORT
      LAYER M5 ;
        RECT  57.264 14.982 57.288 15.066 ;
    END
  END q[245]
  PIN q[246]
    DIRECTION OUTPUT ;
    USE SIGNAL ;
    PORT
      LAYER M5 ;
        RECT  57.504 14.982 57.528 15.066 ;
    END
  END q[246]
  PIN q[247]
    DIRECTION OUTPUT ;
    USE SIGNAL ;
    PORT
      LAYER M5 ;
        RECT  57.696 14.982 57.72 15.066 ;
    END
  END q[247]
  PIN q[248]
    DIRECTION OUTPUT ;
    USE SIGNAL ;
    PORT
      LAYER M5 ;
        RECT  57.888 14.982 57.912 15.066 ;
    END
  END q[248]
  PIN q[249]
    DIRECTION OUTPUT ;
    USE SIGNAL ;
    PORT
      LAYER M5 ;
        RECT  58.128 14.982 58.152 15.066 ;
    END
  END q[249]
  PIN q[24]
    DIRECTION OUTPUT ;
    USE SIGNAL ;
    PORT
      LAYER M5 ;
        RECT  10.464 14.982 10.488 15.066 ;
    END
  END q[24]
  PIN q[250]
    DIRECTION OUTPUT ;
    USE SIGNAL ;
    PORT
      LAYER M5 ;
        RECT  58.32 14.982 58.344 15.066 ;
    END
  END q[250]
  PIN q[251]
    DIRECTION OUTPUT ;
    USE SIGNAL ;
    PORT
      LAYER M5 ;
        RECT  58.56 14.982 58.584 15.066 ;
    END
  END q[251]
  PIN q[252]
    DIRECTION OUTPUT ;
    USE SIGNAL ;
    PORT
      LAYER M5 ;
        RECT  58.752 14.982 58.776 15.066 ;
    END
  END q[252]
  PIN q[253]
    DIRECTION OUTPUT ;
    USE SIGNAL ;
    PORT
      LAYER M5 ;
        RECT  58.944 14.982 58.968 15.066 ;
    END
  END q[253]
  PIN q[254]
    DIRECTION OUTPUT ;
    USE SIGNAL ;
    PORT
      LAYER M5 ;
        RECT  59.184 14.982 59.208 15.066 ;
    END
  END q[254]
  PIN q[255]
    DIRECTION OUTPUT ;
    USE SIGNAL ;
    PORT
      LAYER M5 ;
        RECT  59.376 14.982 59.4 15.066 ;
    END
  END q[255]
  PIN q[25]
    DIRECTION OUTPUT ;
    USE SIGNAL ;
    PORT
      LAYER M5 ;
        RECT  10.704 14.982 10.728 15.066 ;
    END
  END q[25]
  PIN q[26]
    DIRECTION OUTPUT ;
    USE SIGNAL ;
    PORT
      LAYER M5 ;
        RECT  10.896 14.982 10.92 15.066 ;
    END
  END q[26]
  PIN q[27]
    DIRECTION OUTPUT ;
    USE SIGNAL ;
    PORT
      LAYER M5 ;
        RECT  11.088 14.982 11.112 15.066 ;
    END
  END q[27]
  PIN q[28]
    DIRECTION OUTPUT ;
    USE SIGNAL ;
    PORT
      LAYER M5 ;
        RECT  11.328 14.982 11.352 15.066 ;
    END
  END q[28]
  PIN q[29]
    DIRECTION OUTPUT ;
    USE SIGNAL ;
    PORT
      LAYER M5 ;
        RECT  11.52 14.982 11.544 15.066 ;
    END
  END q[29]
  PIN q[2]
    DIRECTION OUTPUT ;
    USE SIGNAL ;
    PORT
      LAYER M5 ;
        RECT  5.808 14.982 5.832 15.066 ;
    END
  END q[2]
  PIN q[30]
    DIRECTION OUTPUT ;
    USE SIGNAL ;
    PORT
      LAYER M5 ;
        RECT  11.76 14.982 11.784 15.066 ;
    END
  END q[30]
  PIN q[31]
    DIRECTION OUTPUT ;
    USE SIGNAL ;
    PORT
      LAYER M5 ;
        RECT  11.952 14.982 11.976 15.066 ;
    END
  END q[31]
  PIN q[32]
    DIRECTION OUTPUT ;
    USE SIGNAL ;
    PORT
      LAYER M5 ;
        RECT  12.144 14.982 12.168 15.066 ;
    END
  END q[32]
  PIN q[33]
    DIRECTION OUTPUT ;
    USE SIGNAL ;
    PORT
      LAYER M5 ;
        RECT  12.384 14.982 12.408 15.066 ;
    END
  END q[33]
  PIN q[34]
    DIRECTION OUTPUT ;
    USE SIGNAL ;
    PORT
      LAYER M5 ;
        RECT  12.576 14.982 12.6 15.066 ;
    END
  END q[34]
  PIN q[35]
    DIRECTION OUTPUT ;
    USE SIGNAL ;
    PORT
      LAYER M5 ;
        RECT  12.816 14.982 12.84 15.066 ;
    END
  END q[35]
  PIN q[36]
    DIRECTION OUTPUT ;
    USE SIGNAL ;
    PORT
      LAYER M5 ;
        RECT  13.008 14.982 13.032 15.066 ;
    END
  END q[36]
  PIN q[37]
    DIRECTION OUTPUT ;
    USE SIGNAL ;
    PORT
      LAYER M5 ;
        RECT  13.104 14.982 13.128 15.066 ;
    END
  END q[37]
  PIN q[38]
    DIRECTION OUTPUT ;
    USE SIGNAL ;
    PORT
      LAYER M5 ;
        RECT  13.584 14.982 13.608 15.066 ;
    END
  END q[38]
  PIN q[39]
    DIRECTION OUTPUT ;
    USE SIGNAL ;
    PORT
      LAYER M5 ;
        RECT  13.68 14.982 13.704 15.066 ;
    END
  END q[39]
  PIN q[3]
    DIRECTION OUTPUT ;
    USE SIGNAL ;
    PORT
      LAYER M5 ;
        RECT  6 14.982 6.024 15.066 ;
    END
  END q[3]
  PIN q[40]
    DIRECTION OUTPUT ;
    USE SIGNAL ;
    PORT
      LAYER M5 ;
        RECT  13.872 14.982 13.896 15.066 ;
    END
  END q[40]
  PIN q[41]
    DIRECTION OUTPUT ;
    USE SIGNAL ;
    PORT
      LAYER M5 ;
        RECT  14.064 14.982 14.088 15.066 ;
    END
  END q[41]
  PIN q[42]
    DIRECTION OUTPUT ;
    USE SIGNAL ;
    PORT
      LAYER M5 ;
        RECT  14.304 14.982 14.328 15.066 ;
    END
  END q[42]
  PIN q[43]
    DIRECTION OUTPUT ;
    USE SIGNAL ;
    PORT
      LAYER M5 ;
        RECT  14.496 14.982 14.52 15.066 ;
    END
  END q[43]
  PIN q[44]
    DIRECTION OUTPUT ;
    USE SIGNAL ;
    PORT
      LAYER M5 ;
        RECT  14.688 14.982 14.712 15.066 ;
    END
  END q[44]
  PIN q[45]
    DIRECTION OUTPUT ;
    USE SIGNAL ;
    PORT
      LAYER M5 ;
        RECT  14.928 14.982 14.952 15.066 ;
    END
  END q[45]
  PIN q[46]
    DIRECTION OUTPUT ;
    USE SIGNAL ;
    PORT
      LAYER M5 ;
        RECT  15.12 14.982 15.144 15.066 ;
    END
  END q[46]
  PIN q[47]
    DIRECTION OUTPUT ;
    USE SIGNAL ;
    PORT
      LAYER M5 ;
        RECT  15.36 14.982 15.384 15.066 ;
    END
  END q[47]
  PIN q[48]
    DIRECTION OUTPUT ;
    USE SIGNAL ;
    PORT
      LAYER M5 ;
        RECT  15.552 14.982 15.576 15.066 ;
    END
  END q[48]
  PIN q[49]
    DIRECTION OUTPUT ;
    USE SIGNAL ;
    PORT
      LAYER M5 ;
        RECT  15.744 14.982 15.768 15.066 ;
    END
  END q[49]
  PIN q[4]
    DIRECTION OUTPUT ;
    USE SIGNAL ;
    PORT
      LAYER M5 ;
        RECT  6.24 14.982 6.264 15.066 ;
    END
  END q[4]
  PIN q[50]
    DIRECTION OUTPUT ;
    USE SIGNAL ;
    PORT
      LAYER M5 ;
        RECT  15.984 14.982 16.008 15.066 ;
    END
  END q[50]
  PIN q[51]
    DIRECTION OUTPUT ;
    USE SIGNAL ;
    PORT
      LAYER M5 ;
        RECT  16.176 14.982 16.2 15.066 ;
    END
  END q[51]
  PIN q[52]
    DIRECTION OUTPUT ;
    USE SIGNAL ;
    PORT
      LAYER M5 ;
        RECT  16.416 14.982 16.44 15.066 ;
    END
  END q[52]
  PIN q[53]
    DIRECTION OUTPUT ;
    USE SIGNAL ;
    PORT
      LAYER M5 ;
        RECT  16.608 14.982 16.632 15.066 ;
    END
  END q[53]
  PIN q[54]
    DIRECTION OUTPUT ;
    USE SIGNAL ;
    PORT
      LAYER M5 ;
        RECT  16.8 14.982 16.824 15.066 ;
    END
  END q[54]
  PIN q[55]
    DIRECTION OUTPUT ;
    USE SIGNAL ;
    PORT
      LAYER M5 ;
        RECT  17.04 14.982 17.064 15.066 ;
    END
  END q[55]
  PIN q[56]
    DIRECTION OUTPUT ;
    USE SIGNAL ;
    PORT
      LAYER M5 ;
        RECT  17.232 14.982 17.256 15.066 ;
    END
  END q[56]
  PIN q[57]
    DIRECTION OUTPUT ;
    USE SIGNAL ;
    PORT
      LAYER M5 ;
        RECT  17.472 14.982 17.496 15.066 ;
    END
  END q[57]
  PIN q[58]
    DIRECTION OUTPUT ;
    USE SIGNAL ;
    PORT
      LAYER M5 ;
        RECT  17.664 14.982 17.688 15.066 ;
    END
  END q[58]
  PIN q[59]
    DIRECTION OUTPUT ;
    USE SIGNAL ;
    PORT
      LAYER M5 ;
        RECT  17.904 14.982 17.928 15.066 ;
    END
  END q[59]
  PIN q[5]
    DIRECTION OUTPUT ;
    USE SIGNAL ;
    PORT
      LAYER M5 ;
        RECT  6.432 14.982 6.456 15.066 ;
    END
  END q[5]
  PIN q[60]
    DIRECTION OUTPUT ;
    USE SIGNAL ;
    PORT
      LAYER M5 ;
        RECT  18.096 14.982 18.12 15.066 ;
    END
  END q[60]
  PIN q[61]
    DIRECTION OUTPUT ;
    USE SIGNAL ;
    PORT
      LAYER M5 ;
        RECT  18.288 14.982 18.312 15.066 ;
    END
  END q[61]
  PIN q[62]
    DIRECTION OUTPUT ;
    USE SIGNAL ;
    PORT
      LAYER M5 ;
        RECT  18.528 14.982 18.552 15.066 ;
    END
  END q[62]
  PIN q[63]
    DIRECTION OUTPUT ;
    USE SIGNAL ;
    PORT
      LAYER M5 ;
        RECT  18.96 14.982 18.984 15.066 ;
    END
  END q[63]
  PIN q[64]
    DIRECTION OUTPUT ;
    USE SIGNAL ;
    PORT
      LAYER M5 ;
        RECT  19.056 14.982 19.08 15.066 ;
    END
  END q[64]
  PIN q[65]
    DIRECTION OUTPUT ;
    USE SIGNAL ;
    PORT
      LAYER M5 ;
        RECT  19.152 14.982 19.176 15.066 ;
    END
  END q[65]
  PIN q[66]
    DIRECTION OUTPUT ;
    USE SIGNAL ;
    PORT
      LAYER M5 ;
        RECT  19.344 14.982 19.368 15.066 ;
    END
  END q[66]
  PIN q[67]
    DIRECTION OUTPUT ;
    USE SIGNAL ;
    PORT
      LAYER M5 ;
        RECT  19.584 14.982 19.608 15.066 ;
    END
  END q[67]
  PIN q[68]
    DIRECTION OUTPUT ;
    USE SIGNAL ;
    PORT
      LAYER M5 ;
        RECT  19.776 14.982 19.8 15.066 ;
    END
  END q[68]
  PIN q[69]
    DIRECTION OUTPUT ;
    USE SIGNAL ;
    PORT
      LAYER M5 ;
        RECT  20.016 14.982 20.04 15.066 ;
    END
  END q[69]
  PIN q[6]
    DIRECTION OUTPUT ;
    USE SIGNAL ;
    PORT
      LAYER M5 ;
        RECT  6.672 14.982 6.696 15.066 ;
    END
  END q[6]
  PIN q[70]
    DIRECTION OUTPUT ;
    USE SIGNAL ;
    PORT
      LAYER M5 ;
        RECT  20.208 14.982 20.232 15.066 ;
    END
  END q[70]
  PIN q[71]
    DIRECTION OUTPUT ;
    USE SIGNAL ;
    PORT
      LAYER M5 ;
        RECT  20.4 14.982 20.424 15.066 ;
    END
  END q[71]
  PIN q[72]
    DIRECTION OUTPUT ;
    USE SIGNAL ;
    PORT
      LAYER M5 ;
        RECT  20.64 14.982 20.664 15.066 ;
    END
  END q[72]
  PIN q[73]
    DIRECTION OUTPUT ;
    USE SIGNAL ;
    PORT
      LAYER M5 ;
        RECT  20.832 14.982 20.856 15.066 ;
    END
  END q[73]
  PIN q[74]
    DIRECTION OUTPUT ;
    USE SIGNAL ;
    PORT
      LAYER M5 ;
        RECT  21.072 14.982 21.096 15.066 ;
    END
  END q[74]
  PIN q[75]
    DIRECTION OUTPUT ;
    USE SIGNAL ;
    PORT
      LAYER M5 ;
        RECT  21.264 14.982 21.288 15.066 ;
    END
  END q[75]
  PIN q[76]
    DIRECTION OUTPUT ;
    USE SIGNAL ;
    PORT
      LAYER M5 ;
        RECT  21.504 14.982 21.528 15.066 ;
    END
  END q[76]
  PIN q[77]
    DIRECTION OUTPUT ;
    USE SIGNAL ;
    PORT
      LAYER M5 ;
        RECT  21.696 14.982 21.72 15.066 ;
    END
  END q[77]
  PIN q[78]
    DIRECTION OUTPUT ;
    USE SIGNAL ;
    PORT
      LAYER M5 ;
        RECT  21.888 14.982 21.912 15.066 ;
    END
  END q[78]
  PIN q[79]
    DIRECTION OUTPUT ;
    USE SIGNAL ;
    PORT
      LAYER M5 ;
        RECT  22.128 14.982 22.152 15.066 ;
    END
  END q[79]
  PIN q[7]
    DIRECTION OUTPUT ;
    USE SIGNAL ;
    PORT
      LAYER M5 ;
        RECT  6.864 14.982 6.888 15.066 ;
    END
  END q[7]
  PIN q[80]
    DIRECTION OUTPUT ;
    USE SIGNAL ;
    PORT
      LAYER M5 ;
        RECT  22.32 14.982 22.344 15.066 ;
    END
  END q[80]
  PIN q[81]
    DIRECTION OUTPUT ;
    USE SIGNAL ;
    PORT
      LAYER M5 ;
        RECT  22.56 14.982 22.584 15.066 ;
    END
  END q[81]
  PIN q[82]
    DIRECTION OUTPUT ;
    USE SIGNAL ;
    PORT
      LAYER M5 ;
        RECT  22.752 14.982 22.776 15.066 ;
    END
  END q[82]
  PIN q[83]
    DIRECTION OUTPUT ;
    USE SIGNAL ;
    PORT
      LAYER M5 ;
        RECT  22.944 14.982 22.968 15.066 ;
    END
  END q[83]
  PIN q[84]
    DIRECTION OUTPUT ;
    USE SIGNAL ;
    PORT
      LAYER M5 ;
        RECT  23.184 14.982 23.208 15.066 ;
    END
  END q[84]
  PIN q[85]
    DIRECTION OUTPUT ;
    USE SIGNAL ;
    PORT
      LAYER M5 ;
        RECT  23.376 14.982 23.4 15.066 ;
    END
  END q[85]
  PIN q[86]
    DIRECTION OUTPUT ;
    USE SIGNAL ;
    PORT
      LAYER M5 ;
        RECT  23.616 14.982 23.64 15.066 ;
    END
  END q[86]
  PIN q[87]
    DIRECTION OUTPUT ;
    USE SIGNAL ;
    PORT
      LAYER M5 ;
        RECT  23.808 14.982 23.832 15.066 ;
    END
  END q[87]
  PIN q[88]
    DIRECTION OUTPUT ;
    USE SIGNAL ;
    PORT
      LAYER M5 ;
        RECT  23.904 14.982 23.928 15.066 ;
    END
  END q[88]
  PIN q[89]
    DIRECTION OUTPUT ;
    USE SIGNAL ;
    PORT
      LAYER M5 ;
        RECT  24.384 14.982 24.408 15.066 ;
    END
  END q[89]
  PIN q[8]
    DIRECTION OUTPUT ;
    USE SIGNAL ;
    PORT
      LAYER M5 ;
        RECT  7.104 14.982 7.128 15.066 ;
    END
  END q[8]
  PIN q[90]
    DIRECTION OUTPUT ;
    USE SIGNAL ;
    PORT
      LAYER M5 ;
        RECT  24.48 14.982 24.504 15.066 ;
    END
  END q[90]
  PIN q[91]
    DIRECTION OUTPUT ;
    USE SIGNAL ;
    PORT
      LAYER M5 ;
        RECT  24.672 14.982 24.696 15.066 ;
    END
  END q[91]
  PIN q[92]
    DIRECTION OUTPUT ;
    USE SIGNAL ;
    PORT
      LAYER M5 ;
        RECT  24.864 14.982 24.888 15.066 ;
    END
  END q[92]
  PIN q[93]
    DIRECTION OUTPUT ;
    USE SIGNAL ;
    PORT
      LAYER M5 ;
        RECT  25.104 14.982 25.128 15.066 ;
    END
  END q[93]
  PIN q[94]
    DIRECTION OUTPUT ;
    USE SIGNAL ;
    PORT
      LAYER M5 ;
        RECT  25.296 14.982 25.32 15.066 ;
    END
  END q[94]
  PIN q[95]
    DIRECTION OUTPUT ;
    USE SIGNAL ;
    PORT
      LAYER M5 ;
        RECT  25.488 14.982 25.512 15.066 ;
    END
  END q[95]
  PIN q[96]
    DIRECTION OUTPUT ;
    USE SIGNAL ;
    PORT
      LAYER M5 ;
        RECT  25.728 14.982 25.752 15.066 ;
    END
  END q[96]
  PIN q[97]
    DIRECTION OUTPUT ;
    USE SIGNAL ;
    PORT
      LAYER M5 ;
        RECT  25.92 14.982 25.944 15.066 ;
    END
  END q[97]
  PIN q[98]
    DIRECTION OUTPUT ;
    USE SIGNAL ;
    PORT
      LAYER M5 ;
        RECT  26.16 14.982 26.184 15.066 ;
    END
  END q[98]
  PIN q[99]
    DIRECTION OUTPUT ;
    USE SIGNAL ;
    PORT
      LAYER M5 ;
        RECT  26.352 14.982 26.376 15.066 ;
    END
  END q[99]
  PIN q[9]
    DIRECTION OUTPUT ;
    USE SIGNAL ;
    PORT
      LAYER M5 ;
        RECT  7.296 14.982 7.32 15.066 ;
    END
  END q[9]
  PIN rst_n
    DIRECTION INPUT ;
    USE SIGNAL ;
    PORT
      LAYER M4 ;
        RECT  0.054 9.696 0.138 9.72 ;
    END
    PORT
      LAYER M4 ;
        RECT  0.108 9.696 0.569 9.72 ;
    END
  END rst_n
  PIN VDD
    DIRECTION INOUT ;
    USE POWER ;
    PORT
      LAYER M5 ;
        RECT  61.992 2.151 62.112 12.969 ;
        RECT  56.592 2.151 56.712 12.969 ;
        RECT  51.192 2.151 51.312 12.969 ;
        RECT  45.792 2.151 45.912 12.969 ;
        RECT  40.392 2.151 40.512 12.969 ;
        RECT  34.992 2.151 35.112 12.969 ;
        RECT  29.592 2.151 29.712 12.969 ;
        RECT  24.192 2.151 24.312 12.969 ;
        RECT  18.792 2.151 18.912 12.969 ;
        RECT  13.392 2.151 13.512 12.969 ;
        RECT  7.992 2.151 8.112 12.969 ;
        RECT  2.592 2.151 2.712 12.969 ;
    END
  END VDD
  PIN VSS
    DIRECTION INOUT ;
    USE GROUND ;
    PORT
      LAYER M5 ;
        RECT  61.8 2.137 61.92 12.983 ;
        RECT  56.4 2.137 56.52 12.983 ;
        RECT  51 2.137 51.12 12.983 ;
        RECT  45.6 2.137 45.72 12.983 ;
        RECT  40.2 2.137 40.32 12.983 ;
        RECT  34.8 2.137 34.92 12.983 ;
        RECT  29.4 2.137 29.52 12.983 ;
        RECT  24 2.137 24.12 12.983 ;
        RECT  18.6 2.137 18.72 12.983 ;
        RECT  13.2 2.137 13.32 12.983 ;
        RECT  7.8 2.137 7.92 12.983 ;
        RECT  2.4 2.137 2.52 12.983 ;
    END
  END VSS
  # OT_OBS_CLOSED layer=M5 d_um=1.536 added=72
  OBS
    LAYER RVTN ;
     RECT  2.16 2.16 62.64 2.295 ;
     RECT  2.16 2.565 62.64 2.835 ;
     RECT  2.16 3.105 62.64 3.375 ;
     RECT  2.16 3.645 62.64 3.915 ;
     RECT  2.16 4.185 62.64 4.455 ;
     RECT  2.16 4.725 62.64 4.995 ;
     RECT  2.16 5.265 62.64 5.535 ;
     RECT  2.16 5.805 62.64 6.075 ;
     RECT  2.16 6.345 62.64 6.615 ;
     RECT  2.16 6.885 62.64 7.155 ;
     RECT  2.16 7.425 62.64 7.695 ;
     RECT  2.16 7.965 62.64 8.235 ;
     RECT  2.16 8.505 62.64 8.775 ;
     RECT  2.16 9.045 62.64 9.315 ;
     RECT  2.16 9.585 62.64 9.855 ;
     RECT  2.16 10.125 62.64 10.395 ;
     RECT  2.16 10.665 62.64 10.935 ;
     RECT  2.16 11.205 62.64 11.475 ;
     RECT  2.16 11.745 62.64 12.015 ;
     RECT  2.16 12.285 62.64 12.555 ;
     RECT  2.16 12.825 62.64 12.96 ;
    LAYER RVTP ;
     RECT  2.16 2.295 62.64 2.565 ;
     RECT  2.16 2.835 62.64 3.105 ;
     RECT  2.16 3.375 62.64 3.645 ;
     RECT  2.16 3.915 62.64 4.185 ;
     RECT  2.16 4.455 62.64 4.725 ;
     RECT  2.16 4.995 62.64 5.265 ;
     RECT  2.16 5.535 62.64 5.805 ;
     RECT  2.16 6.075 62.64 6.345 ;
     RECT  2.16 6.615 62.64 6.885 ;
     RECT  2.16 7.155 62.64 7.425 ;
     RECT  2.16 7.695 62.64 7.965 ;
     RECT  2.16 8.235 62.64 8.505 ;
     RECT  2.16 8.775 62.64 9.045 ;
     RECT  2.16 9.315 62.64 9.585 ;
     RECT  2.16 9.855 62.64 10.125 ;
     RECT  2.16 10.395 62.64 10.665 ;
     RECT  2.16 10.935 62.64 11.205 ;
     RECT  2.16 11.475 62.64 11.745 ;
     RECT  2.16 12.015 62.64 12.285 ;
     RECT  2.16 12.555 62.64 12.825 ;
    LAYER M1 ;
     RECT  2.16 2.151 62.64 12.969 ;
    LAYER M2 ;
     RECT  0.535 9.252 2.16 9.27 ;
     RECT  2.16 2.151 14.035 12.969 ;
     RECT  14.035 2.106 14.135 12.969 ;
     RECT  14.135 2.151 18.355 12.969 ;
     RECT  18.355 2.106 19.751 12.969 ;
     RECT  19.751 2.151 25.663 12.969 ;
     RECT  25.663 2.106 26.159 12.969 ;
     RECT  26.159 2.151 62.64 12.969 ;
    LAYER M3 ;
     RECT  51.264 0.139 51.282 0.523 ;
     RECT  36.468 0.139 36.486 0.571 ;
     RECT  40.356 0.139 40.374 1.099 ;
     RECT  51.156 0.523 51.282 1.099 ;
     RECT  10.188 0.139 10.206 1.147 ;
     RECT  36.468 0.571 37.17 1.675 ;
     RECT  5.22 0.571 5.814 1.723 ;
     RECT  6.84 0.571 6.858 1.723 ;
     RECT  7.956 0.139 7.974 1.723 ;
     RECT  9.576 1.147 10.206 1.723 ;
     RECT  16.56 0.571 16.578 1.723 ;
     RECT  26.784 0.571 27.414 1.723 ;
     RECT  29.772 0.571 29.79 1.723 ;
     RECT  30.744 1.147 30.762 1.723 ;
     RECT  35.82 1.675 37.17 1.723 ;
     RECT  39.816 1.099 40.374 1.723 ;
     RECT  41.616 0.523 41.634 1.723 ;
     RECT  49.032 0.571 49.05 1.723 ;
     RECT  51.156 1.099 51.39 1.723 ;
     RECT  53.064 1.147 53.082 1.723 ;
     RECT  57.06 0.571 57.078 1.723 ;
     RECT  57.888 0.139 57.906 1.723 ;
     RECT  38.736 1.723 44.37 2.191 ;
     RECT  45.324 1.723 59.598 2.191 ;
     RECT  5.22 1.723 31.194 2.251 ;
     RECT  32.148 1.723 32.166 2.251 ;
     RECT  32.976 1.723 37.818 2.251 ;
     RECT  38.628 2.191 59.598 2.251 ;
     RECT  5.22 2.251 32.166 2.299 ;
     RECT  32.976 2.251 59.598 2.299 ;
     RECT  5.22 2.299 59.598 2.371 ;
     RECT  2.415 2.143 2.505 2.413 ;
     RECT  61.815 2.143 61.905 2.413 ;
     RECT  5.22 2.371 59.778 2.803 ;
     RECT  5.22 2.803 59.922 2.911 ;
     RECT  5.112 2.911 59.922 3.271 ;
     RECT  5.112 3.271 59.958 3.403 ;
     RECT  4.788 3.403 59.958 3.443 ;
     RECT  4.896 3.443 59.958 3.721 ;
     RECT  4.896 3.721 60.282 3.847 ;
     RECT  4.896 3.847 60.462 4.145 ;
     RECT  5.328 4.145 60.462 4.289 ;
     RECT  5.796 4.289 60.462 5.611 ;
     RECT  5.004 5.881 5.022 6.151 ;
     RECT  5.796 5.611 60.57 6.151 ;
     RECT  0.54 9.247 0.558 9.725 ;
     RECT  5.004 6.151 60.57 12.209 ;
     RECT  5.004 12.209 60.462 12.479 ;
     RECT  5.112 12.479 60.462 12.515 ;
     RECT  2.415 2.413 2.697 12.707 ;
     RECT  61.815 2.413 62.097 12.707 ;
     RECT  60.444 12.515 60.462 12.785 ;
     RECT  5.112 12.515 59.67 12.857 ;
     RECT  5.112 12.857 30.366 12.893 ;
     RECT  5.436 12.893 30.366 12.941 ;
     RECT  2.415 12.707 2.505 12.977 ;
     RECT  61.815 12.707 61.905 12.977 ;
     RECT  15.3 12.941 30.366 13.085 ;
     RECT  31.14 12.857 59.67 13.085 ;
     RECT  5.436 12.941 14.526 13.613 ;
     RECT  5.436 13.613 13.194 13.661 ;
     RECT  17.64 13.085 23.814 13.661 ;
     RECT  25.128 13.085 25.146 13.661 ;
     RECT  27.756 13.085 30.366 13.661 ;
     RECT  31.14 13.085 37.242 13.661 ;
     RECT  38.052 13.085 45.306 13.661 ;
     RECT  46.368 13.085 55.998 13.661 ;
     RECT  56.988 13.085 57.762 13.661 ;
     RECT  58.572 13.085 59.67 13.661 ;
     RECT  20.088 13.661 23.13 13.709 ;
     RECT  7.236 13.661 9.522 13.757 ;
     RECT  5.436 13.661 6.066 14.237 ;
     RECT  7.236 13.757 7.254 14.237 ;
     RECT  8.388 13.757 9.522 14.237 ;
     RECT  10.728 13.661 12.834 14.237 ;
     RECT  13.968 13.613 14.526 14.237 ;
     RECT  15.3 13.085 16.794 14.237 ;
     RECT  18.072 13.661 19.278 14.237 ;
     RECT  20.088 13.709 23.022 14.237 ;
     RECT  26.064 13.085 26.838 14.237 ;
     RECT  28.332 13.661 30.366 14.237 ;
     RECT  31.14 13.661 32.418 14.237 ;
     RECT  33.372 13.661 36.63 14.237 ;
     RECT  38.16 13.661 39.006 14.237 ;
     RECT  40.644 13.661 45.306 14.237 ;
     RECT  46.476 13.661 54.054 14.237 ;
     RECT  54.864 13.661 55.998 14.237 ;
     RECT  58.572 13.661 58.986 14.237 ;
     RECT  8.388 14.237 9.09 14.285 ;
     RECT  33.912 14.237 36.63 14.285 ;
     RECT  48.384 14.237 48.402 14.285 ;
     RECT  30.024 14.237 30.366 14.717 ;
     RECT  41.688 14.237 41.706 14.765 ;
     RECT  19.08 14.237 19.278 14.909 ;
     RECT  35.748 14.285 36.63 14.909 ;
     RECT  5.796 14.237 5.814 14.957 ;
     RECT  8.388 14.285 8.766 14.957 ;
     RECT  11.232 14.237 11.574 14.957 ;
     RECT  14.148 14.237 14.49 14.957 ;
     RECT  15.3 14.237 15.318 14.957 ;
     RECT  16.776 14.237 16.794 14.957 ;
     RECT  18.072 14.237 18.342 14.957 ;
     RECT  19.26 14.909 19.278 14.957 ;
     RECT  20.088 14.237 21.042 14.957 ;
     RECT  22.032 14.237 23.022 14.957 ;
     RECT  26.1 14.237 26.838 14.957 ;
     RECT  28.332 14.237 28.71 14.957 ;
     RECT  30.024 14.717 30.042 14.957 ;
     RECT  32.4 14.237 32.418 14.957 ;
     RECT  33.912 14.285 34.614 14.957 ;
     RECT  35.748 14.909 36.486 14.957 ;
     RECT  38.16 14.237 38.178 14.957 ;
     RECT  38.988 14.237 39.006 14.957 ;
     RECT  42.588 14.237 42.606 14.957 ;
     RECT  43.74 14.237 44.154 14.957 ;
     RECT  49.356 14.237 50.634 14.957 ;
     RECT  51.66 14.237 51.678 14.957 ;
     RECT  54.036 14.237 54.054 14.957 ;
     RECT  54.936 14.237 54.954 14.957 ;
     RECT  57.456 13.661 57.762 14.957 ;
     RECT  58.968 14.237 58.986 14.957 ;
    LAYER M4 ;
     RECT  0.133 3.888 2.408 3.912 ;
     RECT  2.408 2.148 2.512 12.972 ;
     RECT  2.512 2.418 2.704 12.702 ;
     RECT  2.704 3.888 4.777 3.912 ;
     RECT  4.777 3.408 4.885 3.912 ;
     RECT  5.381 14.208 5.785 14.232 ;
     RECT  5.785 14.208 5.869 14.952 ;
     RECT  5.869 14.208 6.077 14.232 ;
     RECT  5.533 1.728 6.109 1.752 ;
     RECT  6.109 1.728 6.181 2.28 ;
     RECT  4.885 3.408 6.181 4.104 ;
     RECT  6.181 1.728 6.221 4.104 ;
     RECT  5.597 13.056 6.389 13.08 ;
     RECT  6.389 13.056 6.661 13.656 ;
     RECT  6.661 12.912 6.833 13.656 ;
     RECT  6.221 3.888 6.865 4.104 ;
     RECT  6.721 5.136 6.865 5.16 ;
     RECT  5.209 0.576 6.913 0.6 ;
     RECT  6.833 13.056 7.093 13.656 ;
     RECT  7.093 13.056 7.265 14.232 ;
     RECT  6.865 3.888 7.405 5.16 ;
     RECT  6.221 1.728 7.808 2.856 ;
     RECT  7.405 3.888 7.808 5.496 ;
     RECT  7.265 13.056 7.808 13.752 ;
     RECT  7.808 1.728 8.104 13.752 ;
     RECT  7.945 0.144 8.195 0.168 ;
     RECT  8.104 13.632 8.201 13.752 ;
     RECT  8.245 14.208 8.333 14.232 ;
     RECT  8.104 1.728 8.387 1.8 ;
     RECT  8.333 14.208 8.777 14.952 ;
     RECT  8.777 14.208 9.101 14.28 ;
     RECT  9.101 14.208 9.533 14.232 ;
     RECT  8.387 1.728 9.565 1.752 ;
     RECT  9.589 13.056 9.677 13.08 ;
     RECT  8.104 3.888 9.709 5.496 ;
     RECT  8.104 2.832 9.925 2.856 ;
     RECT  9.709 3.888 9.925 5.736 ;
     RECT  9.925 2.832 9.965 5.736 ;
     RECT  9.565 1.152 10.067 1.752 ;
     RECT  10.177 0.144 10.307 0.168 ;
     RECT  9.829 13.632 10.333 13.656 ;
     RECT  9.965 3.408 10.577 5.736 ;
     RECT  9.961 11.376 10.829 11.4 ;
     RECT  10.021 12.528 10.829 12.552 ;
     RECT  10.673 14.208 11.077 14.232 ;
     RECT  10.577 3.888 11.297 5.736 ;
     RECT  10.067 1.728 11.556 1.752 ;
     RECT  11.077 14.208 11.585 14.952 ;
     RECT  11.556 1.728 11.977 1.8 ;
     RECT  11.293 2.832 11.977 2.856 ;
     RECT  11.297 5.712 11.977 5.736 ;
     RECT  11.977 1.728 12.229 2.856 ;
     RECT  11.297 3.888 12.229 4.584 ;
     RECT  12.229 1.728 12.445 4.584 ;
     RECT  12.445 1.728 12.517 4.632 ;
     RECT  11.977 5.712 12.517 6.072 ;
     RECT  11.585 14.208 12.845 14.232 ;
     RECT  11.285 13.056 13.093 13.08 ;
     RECT  12.517 1.728 13.208 6.072 ;
     RECT  13.093 13.056 13.208 13.656 ;
     RECT  13.208 1.728 13.504 13.656 ;
     RECT  13.504 13.056 13.637 13.656 ;
     RECT  13.504 2.784 13.673 6.408 ;
     RECT  13.673 2.928 13.745 6.408 ;
     RECT  13.637 13.584 13.817 13.656 ;
     RECT  13.861 14.208 14.053 14.232 ;
     RECT  13.504 1.728 14.249 1.8 ;
     RECT  14.053 14.208 14.537 14.952 ;
     RECT  13.745 3.696 14.573 6.408 ;
     RECT  14.573 3.696 14.749 6.264 ;
     RECT  14.677 12.912 14.917 12.936 ;
     RECT  14.749 3.408 14.969 6.264 ;
     RECT  14.917 12.528 15.041 12.936 ;
     RECT  14.969 3.408 15.109 5.832 ;
     RECT  14.537 14.928 15.329 14.952 ;
     RECT  15.109 2.88 15.509 5.832 ;
     RECT  15.509 2.88 15.613 5.736 ;
     RECT  14.249 1.728 15.721 1.752 ;
     RECT  15.613 2.832 15.721 5.736 ;
     RECT  15.505 14.208 16.121 14.232 ;
     RECT  15.325 13.056 16.165 13.08 ;
     RECT  15.721 1.728 16.478 5.736 ;
     RECT  16.549 0.576 16.643 0.6 ;
     RECT  16.165 13.056 17.009 13.656 ;
     RECT  16.981 10.8 17.093 10.824 ;
     RECT  17.009 13.008 17.093 13.656 ;
     RECT  16.478 2.736 17.345 5.736 ;
     RECT  17.345 3.072 17.525 5.736 ;
     RECT  17.093 13.056 17.633 13.656 ;
     RECT  17.633 13.584 18.131 13.656 ;
     RECT  16.597 14.928 18.485 14.952 ;
     RECT  16.478 1.728 18.608 1.752 ;
     RECT  17.525 3.072 18.608 4.2 ;
     RECT  17.525 5.184 18.608 5.736 ;
     RECT  18.529 12 18.608 12.024 ;
     RECT  18.608 1.728 18.904 12.972 ;
     RECT  18.485 14.208 19.001 14.952 ;
     RECT  19.001 14.88 19.187 14.952 ;
     RECT  19.313 13.056 19.573 13.08 ;
     RECT  19.573 13.056 19.793 13.656 ;
     RECT  18.904 1.728 20.012 1.848 ;
     RECT  18.904 3.072 20.012 5.736 ;
     RECT  19.187 14.928 20.629 14.952 ;
     RECT  19.793 13.056 21.481 13.08 ;
     RECT  20.012 1.728 21.541 5.736 ;
     RECT  21.481 12.528 21.565 13.08 ;
     RECT  21.541 1.728 21.593 5.784 ;
     RECT  21.593 2.88 21.628 5.784 ;
     RECT  21.593 1.728 21.953 1.896 ;
     RECT  21.565 13.056 22.177 13.08 ;
     RECT  21.628 2.88 22.739 5.736 ;
     RECT  20.629 14.208 22.787 14.952 ;
     RECT  21.953 1.728 22.817 1.848 ;
     RECT  22.787 14.928 23.033 14.952 ;
     RECT  23.101 13.68 23.219 13.704 ;
     RECT  22.739 2.88 23.245 5.592 ;
     RECT  23.365 13.632 23.572 13.656 ;
     RECT  23.572 13.584 23.857 13.656 ;
     RECT  23.857 13.056 23.869 13.656 ;
     RECT  22.817 1.728 24.008 1.8 ;
     RECT  23.245 2.832 24.008 5.592 ;
     RECT  23.821 10.8 24.008 10.824 ;
     RECT  23.869 13.056 24.008 13.08 ;
     RECT  24.008 1.728 24.304 13.08 ;
     RECT  24.304 12.528 25.073 13.08 ;
     RECT  25.073 12.528 25.157 13.656 ;
     RECT  25.157 12.528 25.337 13.08 ;
     RECT  24.304 3.6 25.621 5.64 ;
     RECT  25.717 14.208 25.909 14.232 ;
     RECT  25.621 3.024 25.913 5.64 ;
     RECT  25.909 14.208 26.093 14.952 ;
     RECT  25.337 13.056 26.201 13.08 ;
     RECT  25.913 3.024 26.243 5.208 ;
     RECT  26.269 13.632 26.387 13.656 ;
     RECT  24.304 1.728 26.809 1.8 ;
     RECT  26.243 3.024 26.809 4.68 ;
     RECT  26.093 14.928 26.86 14.952 ;
     RECT  26.809 1.728 27.011 4.68 ;
     RECT  26.533 12.528 27.029 12.552 ;
     RECT  27.02 5.712 27.107 5.736 ;
     RECT  27.197 13.056 27.397 13.08 ;
     RECT  26.773 0.576 27.469 0.6 ;
     RECT  27.397 13.056 27.893 13.656 ;
     RECT  27.011 2.88 28.069 4.68 ;
     RECT  28.069 2.88 28.115 5.592 ;
     RECT  27.997 6.624 28.115 6.648 ;
     RECT  28.115 2.88 28.361 4.344 ;
     RECT  28.115 5.472 28.465 5.592 ;
     RECT  27.011 1.728 28.753 1.752 ;
     RECT  28.021 14.928 28.765 14.952 ;
     RECT  28.361 3.408 29.077 4.344 ;
     RECT  28.465 5.472 29.077 5.832 ;
     RECT  27.893 13.584 29.077 13.656 ;
     RECT  28.753 1.728 29.221 1.848 ;
     RECT  29.077 13.584 29.257 14.232 ;
     RECT  29.221 1.728 29.408 2.04 ;
     RECT  29.077 3.408 29.408 5.832 ;
     RECT  29.257 13.056 29.408 14.232 ;
     RECT  29.408 1.728 29.704 14.232 ;
     RECT  29.704 3.408 29.837 5.832 ;
     RECT  29.704 1.728 29.917 1.8 ;
     RECT  29.837 3.408 29.917 5.688 ;
     RECT  29.704 7.44 29.917 7.464 ;
     RECT  29.704 12.528 29.941 14.232 ;
     RECT  29.761 0.576 29.987 0.6 ;
     RECT  29.941 12.528 30.053 14.952 ;
     RECT  30.053 12.528 30.089 14.712 ;
     RECT  29.917 3.408 30.305 5.544 ;
     RECT  30.089 14.208 30.421 14.712 ;
     RECT  29.917 1.728 30.733 1.752 ;
     RECT  30.089 12.528 30.773 13.08 ;
     RECT  30.733 1.152 30.851 1.752 ;
     RECT  30.773 13.008 31.241 13.08 ;
     RECT  30.305 3.408 31.309 4.536 ;
     RECT  30.305 5.52 31.309 5.544 ;
     RECT  30.851 1.728 31.333 1.752 ;
     RECT  31.309 3.408 31.333 5.544 ;
     RECT  31.273 6.576 31.333 6.6 ;
     RECT  31.333 3.408 31.379 6.888 ;
     RECT  31.333 1.728 31.429 2.28 ;
     RECT  31.429 1.728 31.573 2.328 ;
     RECT  31.379 3.408 31.573 5.688 ;
     RECT  31.379 6.864 31.601 6.888 ;
     RECT  31.241 13.056 31.621 13.08 ;
     RECT  30.421 14.208 31.621 14.232 ;
     RECT  31.573 1.728 31.997 5.688 ;
     RECT  31.997 1.728 32.051 5.256 ;
     RECT  31.621 13.056 32.141 14.232 ;
     RECT  32.293 14.928 32.429 14.952 ;
     RECT  32.141 13.056 32.861 13.704 ;
     RECT  32.051 1.728 32.88 5.208 ;
     RECT  32.857 8.544 33.059 8.568 ;
     RECT  32.88 3.312 33.397 5.208 ;
     RECT  33.109 14.208 33.401 14.232 ;
     RECT  32.861 13.056 33.541 13.08 ;
     RECT  33.397 3.312 33.635 5.736 ;
     RECT  33.541 12.912 33.973 13.08 ;
     RECT  33.973 12.912 34.057 13.656 ;
     RECT  32.88 1.728 34.405 2.28 ;
     RECT  33.635 3.312 34.405 5.304 ;
     RECT  34.057 12.912 34.652 13.08 ;
     RECT  34.652 12.528 34.769 13.08 ;
     RECT  34.405 1.728 34.808 5.304 ;
     RECT  34.769 12.528 34.808 12.972 ;
     RECT  34.808 1.728 34.912 12.972 ;
     RECT  34.912 1.728 35.104 12.936 ;
     RECT  33.733 14.928 35.269 14.952 ;
     RECT  35.104 12.912 35.525 12.936 ;
     RECT  35.269 14.256 35.653 14.952 ;
     RECT  35.104 1.728 35.795 5.736 ;
     RECT  35.795 1.728 35.809 1.752 ;
     RECT  35.795 2.784 35.843 5.736 ;
     RECT  35.809 1.68 35.939 1.752 ;
     RECT  35.653 14.208 36.085 14.952 ;
     RECT  36.085 14.16 36.461 14.952 ;
     RECT  35.843 3.984 36.467 5.736 ;
     RECT  36.461 14.88 36.497 14.952 ;
     RECT  36.457 0.144 36.563 0.168 ;
     RECT  36.497 14.88 36.641 14.904 ;
     RECT  36.889 12 36.995 12.024 ;
     RECT  35.843 2.784 37.045 2.952 ;
     RECT  36.467 3.984 37.045 5.208 ;
     RECT  37.045 2.784 37.091 5.208 ;
     RECT  36.701 13.056 37.141 13.08 ;
     RECT  37.141 0.576 37.225 0.6 ;
     RECT  35.939 1.728 37.333 1.752 ;
     RECT  37.141 13.056 38.081 13.656 ;
     RECT  37.333 1.728 38.243 2.424 ;
     RECT  38.149 14.928 38.357 14.952 ;
     RECT  38.243 1.728 38.435 2.328 ;
     RECT  38.357 14.208 38.441 14.952 ;
     RECT  37.091 3.408 38.513 5.208 ;
     RECT  38.081 13.056 38.629 13.08 ;
     RECT  38.293 6.288 38.675 6.312 ;
     RECT  38.629 12.912 38.765 13.08 ;
     RECT  38.513 3.936 38.977 5.208 ;
     RECT  38.441 14.928 39.017 14.952 ;
     RECT  38.765 13.056 39.061 13.08 ;
     RECT  38.977 3.936 39.161 5.592 ;
     RECT  38.435 1.728 39.452 2.232 ;
     RECT  39.452 1.728 39.589 2.28 ;
     RECT  39.589 1.728 39.697 2.904 ;
     RECT  39.161 3.936 39.697 5.496 ;
     RECT  39.697 1.728 39.805 5.496 ;
     RECT  39.805 1.104 40.163 5.496 ;
     RECT  40.163 1.728 40.208 5.496 ;
     RECT  39.061 13.056 40.208 13.656 ;
     RECT  40.208 1.728 40.504 13.656 ;
     RECT  40.504 12.528 40.549 13.656 ;
     RECT  40.345 0.144 40.595 0.168 ;
     RECT  40.504 1.728 40.787 5.544 ;
     RECT  40.549 12.528 40.979 14.232 ;
     RECT  40.979 12.528 40.997 12.552 ;
     RECT  40.787 2.832 41.105 5.544 ;
     RECT  41.105 2.832 41.26 3.432 ;
     RECT  40.979 13.632 41.605 14.232 ;
     RECT  41.564 0.528 41.651 0.552 ;
     RECT  41.605 13.632 41.957 14.76 ;
     RECT  41.957 13.056 42.041 14.76 ;
     RECT  41.26 2.88 42.181 3.432 ;
     RECT  41.105 4.464 42.181 5.544 ;
     RECT  42.041 13.632 42.229 14.76 ;
     RECT  42.229 13.632 42.473 14.952 ;
     RECT  42.661 12.528 42.761 12.552 ;
     RECT  40.787 1.728 43.045 1.752 ;
     RECT  42.181 2.88 43.045 5.736 ;
     RECT  42.473 14.208 43.121 14.952 ;
     RECT  43.045 1.728 43.139 5.736 ;
     RECT  43.093 12.96 43.345 13.08 ;
     RECT  43.139 2.88 43.693 5.736 ;
     RECT  43.121 14.928 44.117 14.952 ;
     RECT  44.117 14.208 44.165 14.952 ;
     RECT  43.693 2.88 44.189 5.784 ;
     RECT  44.189 2.88 44.197 5.832 ;
     RECT  43.139 1.728 44.521 1.752 ;
     RECT  44.197 2.832 44.521 5.832 ;
     RECT  43.345 13.056 44.773 13.08 ;
     RECT  44.165 14.208 44.773 14.232 ;
     RECT  44.773 13.056 44.993 14.232 ;
     RECT  44.993 14.208 45.317 14.232 ;
     RECT  44.993 13.056 45.452 13.08 ;
     RECT  44.521 1.728 45.493 5.832 ;
     RECT  45.493 1.728 45.608 6.024 ;
     RECT  45.452 13.008 45.608 13.08 ;
     RECT  45.608 1.728 45.904 13.08 ;
     RECT  45.904 2.88 46.019 5.784 ;
     RECT  45.904 12.48 46.073 13.08 ;
     RECT  45.904 1.728 46.115 1.848 ;
     RECT  46.073 12.48 46.115 12.552 ;
     RECT  46.261 13.632 46.421 13.656 ;
     RECT  46.115 12.528 46.757 12.552 ;
     RECT  46.019 2.88 46.829 5.544 ;
     RECT  46.421 13.632 47.441 14.232 ;
     RECT  46.115 1.728 47.468 1.752 ;
     RECT  46.829 2.88 47.468 3.432 ;
     RECT  46.829 4.512 47.939 5.544 ;
     RECT  47.468 1.728 48.044 3.432 ;
     RECT  47.939 4.512 48.044 5.496 ;
     RECT  48.044 1.728 48.131 5.496 ;
     RECT  47.441 14.208 48.133 14.232 ;
     RECT  48.133 14.208 48.773 14.28 ;
     RECT  48.977 0.576 49.061 0.6 ;
     RECT  47.749 13.056 49.157 13.08 ;
     RECT  49.157 13.056 49.241 13.656 ;
     RECT  48.131 1.728 49.489 2.952 ;
     RECT  48.131 3.984 49.489 5.496 ;
     RECT  49.241 13.056 49.621 13.08 ;
     RECT  49.489 1.728 50.569 5.496 ;
     RECT  49.621 12.528 50.605 13.08 ;
     RECT  50.605 11.904 50.636 13.08 ;
     RECT  50.569 1.728 50.725 6.312 ;
     RECT  50.636 11.904 50.885 13.704 ;
     RECT  48.997 14.928 50.885 14.952 ;
     RECT  50.885 11.904 50.969 14.952 ;
     RECT  50.725 1.728 51.008 7.128 ;
     RECT  50.969 11.904 51.008 13.656 ;
     RECT  51.145 0.528 51.253 0.552 ;
     RECT  51.008 1.728 51.304 13.656 ;
     RECT  51.253 0.144 51.361 0.552 ;
     RECT  51.304 1.728 51.361 1.752 ;
     RECT  51.361 0.144 51.491 1.752 ;
     RECT  51.304 13.056 51.517 13.656 ;
     RECT  50.969 14.928 51.689 14.952 ;
     RECT  51.491 1.104 52.019 1.752 ;
     RECT  51.304 2.832 52.405 5.256 ;
     RECT  51.517 13.056 52.549 13.08 ;
     RECT  51.973 14.208 52.549 14.232 ;
     RECT  52.019 1.728 52.765 1.752 ;
     RECT  52.441 6.624 52.796 6.648 ;
     RECT  52.765 1.728 52.892 1.848 ;
     RECT  52.405 2.832 52.892 5.304 ;
     RECT  52.892 1.728 52.933 5.304 ;
     RECT  52.796 6.624 52.933 6.792 ;
     RECT  52.933 1.728 53.053 6.792 ;
     RECT  53.053 1.152 53.507 6.792 ;
     RECT  53.507 2.832 53.593 6.792 ;
     RECT  53.593 2.832 53.603 6.888 ;
     RECT  53.603 6.624 53.633 6.888 ;
     RECT  53.633 6.864 53.677 6.888 ;
     RECT  52.549 13.056 53.893 14.232 ;
     RECT  53.507 1.152 53.939 1.8 ;
     RECT  53.603 2.832 53.993 5.592 ;
     RECT  53.993 3.408 54.065 5.592 ;
     RECT  53.893 13.056 54.137 14.952 ;
     RECT  54.065 5.184 54.173 5.592 ;
     RECT  54.277 12.528 54.461 12.552 ;
     RECT  54.137 13.632 54.713 14.952 ;
     RECT  54.713 14.208 55.009 14.952 ;
     RECT  54.065 3.408 55.537 4.008 ;
     RECT  54.173 5.184 55.537 5.208 ;
     RECT  55.141 13.056 55.745 13.08 ;
     RECT  55.009 14.208 55.745 14.232 ;
     RECT  55.745 13.056 56.053 14.232 ;
     RECT  55.537 3.408 56.185 5.208 ;
     RECT  56.053 13.056 56.197 13.656 ;
     RECT  53.939 1.728 56.285 1.8 ;
     RECT  56.285 1.728 56.408 1.848 ;
     RECT  56.185 3.12 56.408 5.208 ;
     RECT  56.197 12.528 56.408 13.656 ;
     RECT  56.408 1.728 56.704 13.656 ;
     RECT  56.704 1.728 56.819 5.352 ;
     RECT  56.704 12.528 57.017 13.656 ;
     RECT  57.049 0.576 57.133 0.6 ;
     RECT  57.017 12.528 57.341 13.08 ;
     RECT  57.253 14.928 57.773 14.952 ;
     RECT  56.819 1.728 57.809 5.064 ;
     RECT  57.253 0.144 57.917 0.168 ;
     RECT  57.341 13.056 58.309 13.08 ;
     RECT  58.117 14.208 58.601 14.232 ;
     RECT  58.309 12.528 58.673 13.08 ;
     RECT  58.673 12.72 58.741 13.08 ;
     RECT  57.809 2.832 58.889 5.064 ;
     RECT  58.913 14.928 58.997 14.952 ;
     RECT  58.889 4.128 59.125 5.064 ;
     RECT  59.125 4.128 59.171 5.16 ;
     RECT  57.809 1.728 59.219 1.8 ;
     RECT  59.171 5.136 59.321 5.16 ;
     RECT  58.741 12.72 59.429 13.656 ;
     RECT  59.219 1.728 59.609 1.752 ;
     RECT  59.429 13.632 59.681 13.656 ;
     RECT  61.808 2.148 61.912 12.972 ;
     RECT  61.912 2.418 62.104 12.702 ;
    LAYER M5 ;
     RECT  5.424 0.08 59.4 0.611 ;
     RECT  5.616 0.611 59.4 1.763 ;
     RECT  6.672 1.763 8.376 1.811 ;
     RECT  11.76 1.763 13.704 1.811 ;
     RECT  18.6 1.763 25.944 1.811 ;
     RECT  28.896 1.763 29.88 1.811 ;
     RECT  31.344 1.763 35.784 1.811 ;
     RECT  52.8 1.763 59.208 1.811 ;
     RECT  18.6 1.811 22.776 1.859 ;
     RECT  28.896 1.811 29.712 1.859 ;
     RECT  44.16 1.763 46.104 1.859 ;
     RECT  52.8 1.811 53.496 1.859 ;
     RECT  56.304 1.811 57.576 1.859 ;
     RECT  20.064 1.859 21.912 1.907 ;
     RECT  29.328 1.859 29.712 2.051 ;
     RECT  2.4 2.137 2.52 2.151 ;
     RECT  61.8 2.137 61.92 2.151 ;
     RECT  6.672 1.811 8.112 2.291 ;
     RECT  20.064 1.907 21.576 2.291 ;
     RECT  26.976 1.763 27 2.291 ;
     RECT  31.344 1.811 33.144 2.291 ;
     RECT  34.176 1.811 35.784 2.291 ;
     RECT  37.344 1.763 40.776 2.291 ;
     RECT  43.104 1.763 43.128 2.291 ;
     RECT  47.52 1.763 51.312 2.291 ;
     RECT  12.576 1.811 13.512 2.339 ;
     RECT  15.12 1.763 16.44 2.339 ;
     RECT  37.344 2.291 38.664 2.435 ;
     RECT  34.416 2.291 35.784 2.773 ;
     RECT  37.344 2.435 37.56 2.773 ;
     RECT  12.672 2.339 13.512 2.821 ;
     RECT  16.416 2.339 16.44 2.821 ;
     RECT  40.2 2.291 40.776 2.821 ;
     RECT  15.12 2.339 15.144 2.915 ;
     RECT  12.672 2.821 13.608 2.917 ;
     RECT  20.064 2.291 20.088 3.107 ;
     RECT  44.16 1.859 45.912 3.109 ;
     RECT  21.504 2.291 21.576 3.205 ;
     RECT  31.344 2.291 33.048 3.301 ;
     RECT  34.416 2.773 37.56 3.301 ;
     RECT  18.6 1.859 18.912 3.349 ;
     RECT  52.944 1.859 53.496 3.349 ;
     RECT  50.784 2.291 51.312 3.397 ;
     RECT  12.672 2.917 13.656 3.443 ;
     RECT  16.416 2.821 16.488 3.443 ;
     RECT  40.2 2.821 41.208 3.443 ;
     RECT  31.344 3.301 37.56 3.491 ;
     RECT  48.912 2.291 48.936 3.733 ;
     RECT  16.416 3.443 16.44 3.781 ;
     RECT  21.504 3.205 21.768 3.781 ;
     RECT  31.344 3.491 37.08 3.827 ;
     RECT  43.488 3.109 45.912 3.829 ;
     RECT  31.584 3.827 37.08 3.875 ;
     RECT  16.08 3.781 16.44 3.923 ;
     RECT  18.288 3.349 18.912 3.925 ;
     RECT  42.192 2.917 42.216 3.925 ;
     RECT  43.488 3.829 46.008 3.925 ;
     RECT  52.848 3.349 53.496 3.925 ;
     RECT  18.288 3.925 19.032 4.019 ;
     RECT  31.584 3.875 36.6 4.019 ;
     RECT  42.192 3.925 46.008 4.019 ;
     RECT  48.096 3.733 48.936 4.019 ;
     RECT  56.4 1.859 57.576 4.019 ;
     RECT  29.4 2.051 29.712 4.069 ;
     RECT  29.4 4.069 29.832 4.211 ;
     RECT  12.96 3.443 13.656 4.261 ;
     RECT  15.36 3.925 15.384 4.261 ;
     RECT  52.416 3.925 53.496 4.261 ;
     RECT  24 1.811 24.312 4.501 ;
     RECT  48.096 4.019 48.12 4.501 ;
     RECT  18.6 4.019 19.032 4.595 ;
     RECT  27.072 3.973 27.096 4.645 ;
     RECT  21.504 3.781 22.728 4.693 ;
     RECT  38.64 2.435 38.664 4.693 ;
     RECT  40.2 3.443 40.512 4.693 ;
     RECT  38.64 4.693 40.512 4.741 ;
     RECT  38.64 4.741 41.352 4.979 ;
     RECT  40.2 4.979 41.352 5.077 ;
     RECT  42.72 4.019 46.008 5.077 ;
     RECT  12.96 4.261 15.384 5.171 ;
     RECT  21.36 4.693 22.728 5.171 ;
     RECT  31.584 4.019 33.624 5.171 ;
     RECT  47.712 4.501 48.12 5.171 ;
     RECT  59.136 4.117 59.16 5.171 ;
     RECT  24 4.501 24.792 5.219 ;
     RECT  26.208 4.645 27.096 5.219 ;
     RECT  31.584 5.171 32.04 5.267 ;
     RECT  16.416 3.923 16.44 5.315 ;
     RECT  52.416 4.261 53.592 5.315 ;
     RECT  56.4 4.019 56.808 5.363 ;
     RECT  0.144 3.877 0.168 5.411 ;
     RECT  34.8 4.019 36.456 5.459 ;
     RECT  47.712 5.171 47.928 5.459 ;
     RECT  21.36 5.171 21.576 5.507 ;
     RECT  40.2 5.077 46.008 5.507 ;
     RECT  47.904 5.459 47.928 5.555 ;
     RECT  52.848 5.315 53.592 5.557 ;
     RECT  29.4 4.211 29.712 5.653 ;
     RECT  13.2 5.171 15.384 5.747 ;
     RECT  22.704 5.171 22.728 5.747 ;
     RECT  27.072 5.219 27.096 5.747 ;
     RECT  33.024 5.171 33.624 5.747 ;
     RECT  36.432 5.459 36.456 5.747 ;
     RECT  42.192 5.507 46.008 5.747 ;
     RECT  21.552 5.507 21.576 5.795 ;
     RECT  43.728 5.747 46.008 5.795 ;
     RECT  44.208 5.795 45.912 5.843 ;
     RECT  45.504 5.843 45.912 6.035 ;
     RECT  38.64 4.979 38.664 6.323 ;
     RECT  50.592 3.397 51.312 6.323 ;
     RECT  13.2 5.747 13.656 6.419 ;
     RECT  28.08 4.645 28.104 6.659 ;
     RECT  52.848 5.557 53.64 6.803 ;
     RECT  31.344 5.509 31.368 6.899 ;
     RECT  53.616 6.803 53.64 6.899 ;
     RECT  50.736 6.323 51.312 7.139 ;
     RECT  29.4 5.653 29.88 7.475 ;
     RECT  33.024 5.747 33.048 8.579 ;
     RECT  45.6 6.035 45.912 12.469 ;
     RECT  24 5.219 24.312 12.517 ;
     RECT  29.4 7.475 29.712 12.517 ;
     RECT  34.8 5.459 35.112 12.517 ;
     RECT  40.2 5.507 40.512 12.517 ;
     RECT  45.6 12.469 46.104 12.517 ;
     RECT  51 7.139 51.312 12.517 ;
     RECT  56.4 5.363 56.712 12.517 ;
     RECT  58.32 12.517 58.344 12.709 ;
     RECT  14.928 12.517 14.952 12.901 ;
     RECT  34.704 12.517 35.112 12.901 ;
     RECT  42.672 12.517 42.696 12.949 ;
     RECT  2.4 2.151 2.712 12.969 ;
     RECT  61.8 2.151 62.112 12.969 ;
     RECT  2.4 12.969 2.52 12.983 ;
     RECT  18.6 4.595 18.912 12.983 ;
     RECT  61.8 12.969 61.92 12.983 ;
     RECT  29.4 12.517 30.6 12.997 ;
     RECT  45.6 12.517 46.728 12.997 ;
     RECT  6.672 12.901 6.696 13.045 ;
     RECT  7.8 2.291 8.112 13.045 ;
     RECT  10.032 12.517 10.488 13.045 ;
     RECT  13.2 6.419 13.512 13.045 ;
     RECT  14.688 12.901 14.952 13.045 ;
     RECT  17.04 12.997 17.064 13.045 ;
     RECT  21.504 12.517 21.528 13.045 ;
     RECT  24 12.517 25.32 13.045 ;
     RECT  26.544 12.517 27 13.045 ;
     RECT  29.4 12.997 31.224 13.045 ;
     RECT  33.552 12.901 33.576 13.045 ;
     RECT  34.704 12.901 35.208 13.045 ;
     RECT  36.96 11.989 36.984 13.045 ;
     RECT  38.64 12.901 38.664 13.045 ;
     RECT  40.2 12.517 40.776 13.045 ;
     RECT  42.672 12.949 43.32 13.045 ;
     RECT  45.504 12.997 46.728 13.045 ;
     RECT  49.632 12.517 51.312 13.045 ;
     RECT  54.288 12.517 54.312 13.045 ;
     RECT  56.208 12.517 57.096 13.045 ;
     RECT  58.32 12.709 59.208 13.045 ;
     RECT  36.72 13.045 40.776 13.093 ;
     RECT  9.6 13.045 13.608 13.573 ;
     RECT  14.688 13.045 17.496 13.573 ;
     RECT  23.904 13.045 27.864 13.573 ;
     RECT  29.328 13.045 31.896 13.573 ;
     RECT  5.616 13.045 8.112 13.621 ;
     RECT  23.616 13.573 31.896 13.621 ;
     RECT  32.928 13.045 35.208 13.621 ;
     RECT  36.72 13.093 40.968 13.621 ;
     RECT  42 13.045 46.728 13.621 ;
     RECT  47.76 13.045 52.44 13.621 ;
     RECT  53.472 13.045 59.208 13.621 ;
     RECT  23.376 13.621 35.208 13.669 ;
     RECT  23.184 13.669 35.208 14.149 ;
     RECT  36.72 13.621 59.4 14.149 ;
     RECT  5.616 13.621 8.184 14.197 ;
     RECT  9.6 13.573 13.704 14.197 ;
     RECT  14.688 13.573 18.12 14.197 ;
     RECT  19.344 13.045 22.152 14.197 ;
     RECT  23.184 14.149 59.4 14.197 ;
     RECT  5.424 14.197 59.4 15.024 ;
     RECT  13.704 1.763 15.12 1.811 ;
     RECT  16.44 1.763 16.488 2.821 ;
     RECT  25.944 1.763 26.976 1.811 ;
     RECT  29.88 1.763 31.344 1.811 ;
     RECT  35.784 1.763 37.344 2.773 ;
     RECT  40.776 1.763 43.104 2.291 ;
     RECT  43.128 1.763 44.16 2.291 ;
     RECT  46.104 1.763 47.52 1.859 ;
     RECT  51.312 1.763 52.8 1.859 ;
     RECT  13.512 1.811 15.12 2.821 ;
     RECT  22.776 1.811 24 1.859 ;
     RECT  33.144 1.811 34.176 2.291 ;
     RECT  18.912 1.859 20.064 3.107 ;
     RECT  52.848 1.859 52.944 3.349 ;
     RECT  21.576 1.907 21.768 3.205 ;
     RECT  20.088 2.291 21.504 3.107 ;
     RECT  33.048 2.291 34.416 3.301 ;
     RECT  40.776 2.291 44.16 2.821 ;
     RECT  48.096 2.291 48.912 3.733 ;
     RECT  50.592 2.291 50.784 3.397 ;
     RECT  15.144 2.339 16.416 2.915 ;
     RECT  37.56 2.435 38.64 3.491 ;
     RECT  13.608 2.821 15.12 2.915 ;
     RECT  41.208 2.821 44.16 2.917 ;
     RECT  13.608 2.915 16.416 2.917 ;
     RECT  13.656 2.917 16.416 3.781 ;
     RECT  41.208 2.917 42.192 3.443 ;
     RECT  42.216 2.917 44.16 3.109 ;
     RECT  18.912 3.107 19.032 3.925 ;
     RECT  42.216 3.109 43.488 3.925 ;
     RECT  40.512 3.443 42.192 4.019 ;
     RECT  13.656 3.781 16.08 3.923 ;
     RECT  22.728 3.781 24 5.747 ;
     RECT  13.656 3.923 16.416 3.925 ;
     RECT  13.656 3.925 15.36 4.261 ;
     RECT  15.384 3.925 16.416 5.315 ;
     RECT  51.312 3.925 52.416 5.315 ;
     RECT  33.624 4.019 34.8 5.747 ;
     RECT  40.512 4.019 42.72 4.741 ;
     RECT  29.712 4.211 29.832 5.509 ;
     RECT  24.792 4.645 26.208 5.219 ;
     RECT  27.096 4.645 28.08 5.747 ;
     RECT  28.104 4.645 29.4 6.659 ;
     RECT  41.352 4.741 42.72 5.077 ;
     RECT  21.576 5.171 22.704 5.747 ;
     RECT  32.04 5.171 33.024 5.267 ;
     RECT  35.112 5.459 36.432 5.747 ;
     RECT  29.712 5.509 31.344 5.653 ;
     RECT  29.88 5.653 31.344 6.899 ;
     RECT  13.512 12.517 14.928 12.901 ;
     RECT  25.32 12.517 26.544 13.045 ;
     RECT  57.096 12.517 58.32 13.045 ;
     RECT  6.696 12.901 7.8 13.045 ;
     RECT  13.512 12.901 14.688 13.045 ;
     RECT  33.576 12.901 34.704 13.045 ;
     RECT  18.6 12.983 18.912 13.045 ;
     RECT  8.112 13.045 9.6 13.621 ;
     RECT  13.608 13.045 14.688 13.573 ;
     RECT  17.496 13.045 19.344 13.573 ;
     RECT  27.864 13.045 29.328 13.573 ;
     RECT  31.896 13.045 32.928 13.621 ;
     RECT  35.208 13.045 36.72 14.149 ;
     RECT  40.776 13.045 42 13.093 ;
     RECT  46.728 13.045 47.76 13.621 ;
     RECT  52.44 13.045 53.472 13.621 ;
     RECT  40.968 13.093 42 13.621 ;
     RECT  13.704 13.573 14.688 14.197 ;
     RECT  18.12 13.573 19.344 14.197 ;
     RECT  22.152 13.573 23.616 13.621 ;
     RECT  8.184 13.621 9.6 14.197 ;
     RECT  22.152 13.621 23.376 13.669 ;
     RECT  22.152 13.669 23.184 14.197 ;
  END
END qkh_packet_h256
END LIBRARY
